VERSION 5.8 ;
BUSBITCHARS "[]" ;
DIVIDERCHAR "/" ;
UNITS
    DATABASE MICRONS 1000 ;
END UNITS

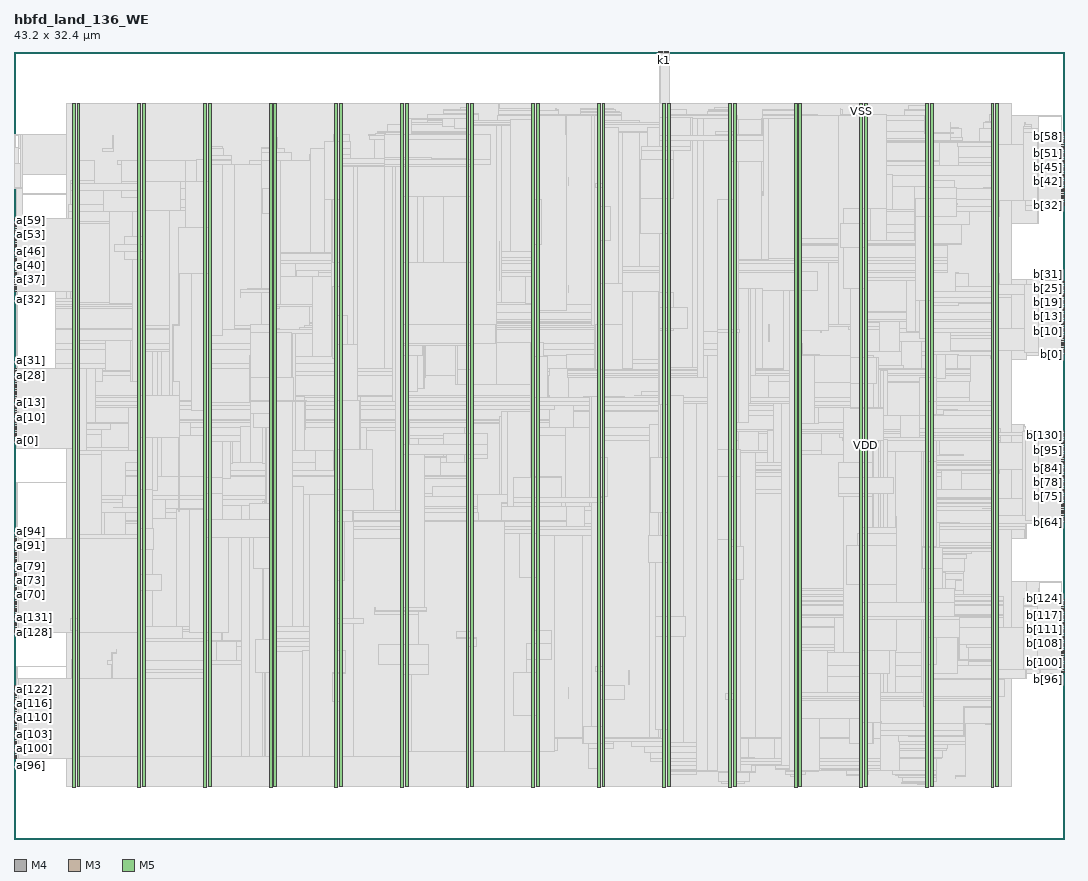
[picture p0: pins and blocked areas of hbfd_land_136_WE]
MACRO hbfd_land_136_WE
  FOREIGN hbfd_land_136_WE 0 0 ;
  CLASS BLOCK ;
  SIZE 43.2 BY 32.4 ;
  PIN a[0]
    DIRECTION INPUT ;
    USE SIGNAL ;
    PORT
      LAYER M4 ;
        RECT  0 16.368 0.084 16.392 ;
    END
  END a[0]
  PIN a[100]
    DIRECTION INPUT ;
    USE SIGNAL ;
    PORT
      LAYER M4 ;
        RECT  0 3.696 0.084 3.72 ;
    END
  END a[100]
  PIN a[101]
    DIRECTION INPUT ;
    USE SIGNAL ;
    PORT
      LAYER M4 ;
        RECT  0 3.792 0.084 3.816 ;
    END
  END a[101]
  PIN a[102]
    DIRECTION INPUT ;
    USE SIGNAL ;
    PORT
      LAYER M4 ;
        RECT  0 3.888 0.084 3.912 ;
    END
  END a[102]
  PIN a[103]
    DIRECTION INPUT ;
    USE SIGNAL ;
    PORT
      LAYER M4 ;
        RECT  0 3.984 0.084 4.008 ;
    END
  END a[103]
  PIN a[104]
    DIRECTION INPUT ;
    USE SIGNAL ;
    PORT
      LAYER M4 ;
        RECT  0 4.08 0.084 4.104 ;
    END
  END a[104]
  PIN a[105]
    DIRECTION INPUT ;
    USE SIGNAL ;
    PORT
      LAYER M4 ;
        RECT  0 4.176 0.084 4.2 ;
    END
  END a[105]
  PIN a[106]
    DIRECTION INPUT ;
    USE SIGNAL ;
    PORT
      LAYER M4 ;
        RECT  0 4.272 0.084 4.296 ;
    END
  END a[106]
  PIN a[107]
    DIRECTION INPUT ;
    USE SIGNAL ;
    PORT
      LAYER M4 ;
        RECT  0 4.368 0.084 4.392 ;
    END
  END a[107]
  PIN a[108]
    DIRECTION INPUT ;
    USE SIGNAL ;
    PORT
      LAYER M4 ;
        RECT  0 4.464 0.084 4.488 ;
    END
  END a[108]
  PIN a[109]
    DIRECTION INPUT ;
    USE SIGNAL ;
    PORT
      LAYER M4 ;
        RECT  0 4.56 0.084 4.584 ;
    END
  END a[109]
  PIN a[10]
    DIRECTION INPUT ;
    USE SIGNAL ;
    PORT
      LAYER M4 ;
        RECT  0 17.328 0.084 17.352 ;
    END
  END a[10]
  PIN a[110]
    DIRECTION INPUT ;
    USE SIGNAL ;
    PORT
      LAYER M4 ;
        RECT  0 4.656 0.084 4.68 ;
    END
  END a[110]
  PIN a[111]
    DIRECTION INPUT ;
    USE SIGNAL ;
    PORT
      LAYER M4 ;
        RECT  0 4.752 0.084 4.776 ;
    END
  END a[111]
  PIN a[112]
    DIRECTION INPUT ;
    USE SIGNAL ;
    PORT
      LAYER M4 ;
        RECT  0 4.848 0.084 4.872 ;
    END
  END a[112]
  PIN a[113]
    DIRECTION INPUT ;
    USE SIGNAL ;
    PORT
      LAYER M4 ;
        RECT  0 4.944 0.084 4.968 ;
    END
  END a[113]
  PIN a[114]
    DIRECTION INPUT ;
    USE SIGNAL ;
    PORT
      LAYER M4 ;
        RECT  0 5.04 0.084 5.064 ;
    END
  END a[114]
  PIN a[115]
    DIRECTION INPUT ;
    USE SIGNAL ;
    PORT
      LAYER M4 ;
        RECT  0 5.136 0.084 5.16 ;
    END
  END a[115]
  PIN a[116]
    DIRECTION INPUT ;
    USE SIGNAL ;
    PORT
      LAYER M4 ;
        RECT  0 5.232 0.084 5.256 ;
    END
  END a[116]
  PIN a[117]
    DIRECTION INPUT ;
    USE SIGNAL ;
    PORT
      LAYER M4 ;
        RECT  0 5.328 0.084 5.352 ;
    END
  END a[117]
  PIN a[118]
    DIRECTION INPUT ;
    USE SIGNAL ;
    PORT
      LAYER M4 ;
        RECT  0 5.424 0.084 5.448 ;
    END
  END a[118]
  PIN a[119]
    DIRECTION INPUT ;
    USE SIGNAL ;
    PORT
      LAYER M4 ;
        RECT  0 5.52 0.084 5.544 ;
    END
  END a[119]
  PIN a[11]
    DIRECTION INPUT ;
    USE SIGNAL ;
    PORT
      LAYER M4 ;
        RECT  0 17.424 0.084 17.448 ;
    END
  END a[11]
  PIN a[120]
    DIRECTION INPUT ;
    USE SIGNAL ;
    PORT
      LAYER M4 ;
        RECT  0 5.616 0.084 5.64 ;
    END
  END a[120]
  PIN a[121]
    DIRECTION INPUT ;
    USE SIGNAL ;
    PORT
      LAYER M4 ;
        RECT  0 5.712 0.084 5.736 ;
    END
  END a[121]
  PIN a[122]
    DIRECTION INPUT ;
    USE SIGNAL ;
    PORT
      LAYER M4 ;
        RECT  0 5.808 0.084 5.832 ;
    END
  END a[122]
  PIN a[123]
    DIRECTION INPUT ;
    USE SIGNAL ;
    PORT
      LAYER M4 ;
        RECT  0 5.904 0.084 5.928 ;
    END
  END a[123]
  PIN a[124]
    DIRECTION INPUT ;
    USE SIGNAL ;
    PORT
      LAYER M4 ;
        RECT  0 6 0.084 6.024 ;
    END
  END a[124]
  PIN a[125]
    DIRECTION INPUT ;
    USE SIGNAL ;
    PORT
      LAYER M4 ;
        RECT  0 6.096 0.084 6.12 ;
    END
  END a[125]
  PIN a[126]
    DIRECTION INPUT ;
    USE SIGNAL ;
    PORT
      LAYER M4 ;
        RECT  0 6.192 0.084 6.216 ;
    END
  END a[126]
  PIN a[127]
    DIRECTION INPUT ;
    USE SIGNAL ;
    PORT
      LAYER M4 ;
        RECT  0 6.288 0.084 6.312 ;
    END
  END a[127]
  PIN a[128]
    DIRECTION INPUT ;
    USE SIGNAL ;
    PORT
      LAYER M4 ;
        RECT  0 8.496 0.084 8.52 ;
    END
  END a[128]
  PIN a[129]
    DIRECTION INPUT ;
    USE SIGNAL ;
    PORT
      LAYER M4 ;
        RECT  0 8.592 0.084 8.616 ;
    END
  END a[129]
  PIN a[12]
    DIRECTION INPUT ;
    USE SIGNAL ;
    PORT
      LAYER M4 ;
        RECT  0 17.52 0.084 17.544 ;
    END
  END a[12]
  PIN a[130]
    DIRECTION INPUT ;
    USE SIGNAL ;
    PORT
      LAYER M4 ;
        RECT  0 8.688 0.084 8.712 ;
    END
  END a[130]
  PIN a[131]
    DIRECTION INPUT ;
    USE SIGNAL ;
    PORT
      LAYER M4 ;
        RECT  0 8.784 0.084 8.808 ;
    END
  END a[131]
  PIN a[132]
    DIRECTION INPUT ;
    USE SIGNAL ;
    PORT
      LAYER M4 ;
        RECT  0 8.88 0.084 8.904 ;
    END
  END a[132]
  PIN a[133]
    DIRECTION INPUT ;
    USE SIGNAL ;
    PORT
      LAYER M4 ;
        RECT  0 8.976 0.084 9 ;
    END
  END a[133]
  PIN a[134]
    DIRECTION INPUT ;
    USE SIGNAL ;
    PORT
      LAYER M4 ;
        RECT  0 9.072 0.084 9.096 ;
    END
  END a[134]
  PIN a[135]
    DIRECTION INPUT ;
    USE SIGNAL ;
    PORT
      LAYER M4 ;
        RECT  0 9.168 0.084 9.192 ;
    END
  END a[135]
  PIN a[13]
    DIRECTION INPUT ;
    USE SIGNAL ;
    PORT
      LAYER M4 ;
        RECT  0 17.616 0.084 17.64 ;
    END
  END a[13]
  PIN a[14]
    DIRECTION INPUT ;
    USE SIGNAL ;
    PORT
      LAYER M4 ;
        RECT  0 17.712 0.084 17.736 ;
    END
  END a[14]
  PIN a[15]
    DIRECTION INPUT ;
    USE SIGNAL ;
    PORT
      LAYER M4 ;
        RECT  0 17.808 0.084 17.832 ;
    END
  END a[15]
  PIN a[16]
    DIRECTION INPUT ;
    USE SIGNAL ;
    PORT
      LAYER M4 ;
        RECT  0 17.904 0.084 17.928 ;
    END
  END a[16]
  PIN a[17]
    DIRECTION INPUT ;
    USE SIGNAL ;
    PORT
      LAYER M4 ;
        RECT  0 18 0.084 18.024 ;
    END
  END a[17]
  PIN a[18]
    DIRECTION INPUT ;
    USE SIGNAL ;
    PORT
      LAYER M4 ;
        RECT  0 18.096 0.084 18.12 ;
    END
  END a[18]
  PIN a[19]
    DIRECTION INPUT ;
    USE SIGNAL ;
    PORT
      LAYER M4 ;
        RECT  0 18.192 0.084 18.216 ;
    END
  END a[19]
  PIN a[1]
    DIRECTION INPUT ;
    USE SIGNAL ;
    PORT
      LAYER M4 ;
        RECT  0 16.464 0.084 16.488 ;
    END
  END a[1]
  PIN a[20]
    DIRECTION INPUT ;
    USE SIGNAL ;
    PORT
      LAYER M4 ;
        RECT  0 18.288 0.084 18.312 ;
    END
  END a[20]
  PIN a[21]
    DIRECTION INPUT ;
    USE SIGNAL ;
    PORT
      LAYER M4 ;
        RECT  0 18.384 0.084 18.408 ;
    END
  END a[21]
  PIN a[22]
    DIRECTION INPUT ;
    USE SIGNAL ;
    PORT
      LAYER M4 ;
        RECT  0 18.48 0.084 18.504 ;
    END
  END a[22]
  PIN a[23]
    DIRECTION INPUT ;
    USE SIGNAL ;
    PORT
      LAYER M4 ;
        RECT  0 18.576 0.084 18.6 ;
    END
  END a[23]
  PIN a[24]
    DIRECTION INPUT ;
    USE SIGNAL ;
    PORT
      LAYER M4 ;
        RECT  0 18.672 0.084 18.696 ;
    END
  END a[24]
  PIN a[25]
    DIRECTION INPUT ;
    USE SIGNAL ;
    PORT
      LAYER M4 ;
        RECT  0 18.768 0.084 18.792 ;
    END
  END a[25]
  PIN a[26]
    DIRECTION INPUT ;
    USE SIGNAL ;
    PORT
      LAYER M4 ;
        RECT  0 18.864 0.084 18.888 ;
    END
  END a[26]
  PIN a[27]
    DIRECTION INPUT ;
    USE SIGNAL ;
    PORT
      LAYER M4 ;
        RECT  0 18.96 0.084 18.984 ;
    END
  END a[27]
  PIN a[28]
    DIRECTION INPUT ;
    USE SIGNAL ;
    PORT
      LAYER M4 ;
        RECT  0 19.056 0.084 19.08 ;
    END
  END a[28]
  PIN a[29]
    DIRECTION INPUT ;
    USE SIGNAL ;
    PORT
      LAYER M4 ;
        RECT  0 19.152 0.084 19.176 ;
    END
  END a[29]
  PIN a[2]
    DIRECTION INPUT ;
    USE SIGNAL ;
    PORT
      LAYER M4 ;
        RECT  0 16.56 0.084 16.584 ;
    END
  END a[2]
  PIN a[30]
    DIRECTION INPUT ;
    USE SIGNAL ;
    PORT
      LAYER M4 ;
        RECT  0 19.248 0.084 19.272 ;
    END
  END a[30]
  PIN a[31]
    DIRECTION INPUT ;
    USE SIGNAL ;
    PORT
      LAYER M4 ;
        RECT  0 19.344 0.084 19.368 ;
    END
  END a[31]
  PIN a[32]
    DIRECTION INPUT ;
    USE SIGNAL ;
    PORT
      LAYER M4 ;
        RECT  0 22.512 0.084 22.536 ;
    END
  END a[32]
  PIN a[33]
    DIRECTION INPUT ;
    USE SIGNAL ;
    PORT
      LAYER M4 ;
        RECT  0 22.608 0.084 22.632 ;
    END
  END a[33]
  PIN a[34]
    DIRECTION INPUT ;
    USE SIGNAL ;
    PORT
      LAYER M4 ;
        RECT  0 22.704 0.084 22.728 ;
    END
  END a[34]
  PIN a[35]
    DIRECTION INPUT ;
    USE SIGNAL ;
    PORT
      LAYER M4 ;
        RECT  0 22.8 0.084 22.824 ;
    END
  END a[35]
  PIN a[36]
    DIRECTION INPUT ;
    USE SIGNAL ;
    PORT
      LAYER M4 ;
        RECT  0 22.896 0.084 22.92 ;
    END
  END a[36]
  PIN a[37]
    DIRECTION INPUT ;
    USE SIGNAL ;
    PORT
      LAYER M4 ;
        RECT  0 22.992 0.084 23.016 ;
    END
  END a[37]
  PIN a[38]
    DIRECTION INPUT ;
    USE SIGNAL ;
    PORT
      LAYER M4 ;
        RECT  0 23.088 0.084 23.112 ;
    END
  END a[38]
  PIN a[39]
    DIRECTION INPUT ;
    USE SIGNAL ;
    PORT
      LAYER M4 ;
        RECT  0 23.184 0.084 23.208 ;
    END
  END a[39]
  PIN a[3]
    DIRECTION INPUT ;
    USE SIGNAL ;
    PORT
      LAYER M4 ;
        RECT  0 16.656 0.084 16.68 ;
    END
  END a[3]
  PIN a[40]
    DIRECTION INPUT ;
    USE SIGNAL ;
    PORT
      LAYER M4 ;
        RECT  0 23.28 0.084 23.304 ;
    END
  END a[40]
  PIN a[41]
    DIRECTION INPUT ;
    USE SIGNAL ;
    PORT
      LAYER M4 ;
        RECT  0 23.376 0.084 23.4 ;
    END
  END a[41]
  PIN a[42]
    DIRECTION INPUT ;
    USE SIGNAL ;
    PORT
      LAYER M4 ;
        RECT  0 23.472 0.084 23.496 ;
    END
  END a[42]
  PIN a[43]
    DIRECTION INPUT ;
    USE SIGNAL ;
    PORT
      LAYER M4 ;
        RECT  0 23.568 0.084 23.592 ;
    END
  END a[43]
  PIN a[44]
    DIRECTION INPUT ;
    USE SIGNAL ;
    PORT
      LAYER M4 ;
        RECT  0 23.664 0.084 23.688 ;
    END
  END a[44]
  PIN a[45]
    DIRECTION INPUT ;
    USE SIGNAL ;
    PORT
      LAYER M4 ;
        RECT  0 23.76 0.084 23.784 ;
    END
  END a[45]
  PIN a[46]
    DIRECTION INPUT ;
    USE SIGNAL ;
    PORT
      LAYER M4 ;
        RECT  0 23.856 0.084 23.88 ;
    END
  END a[46]
  PIN a[47]
    DIRECTION INPUT ;
    USE SIGNAL ;
    PORT
      LAYER M4 ;
        RECT  0 23.952 0.084 23.976 ;
    END
  END a[47]
  PIN a[48]
    DIRECTION INPUT ;
    USE SIGNAL ;
    PORT
      LAYER M4 ;
        RECT  0 24.048 0.084 24.072 ;
    END
  END a[48]
  PIN a[49]
    DIRECTION INPUT ;
    USE SIGNAL ;
    PORT
      LAYER M4 ;
        RECT  0 24.144 0.084 24.168 ;
    END
  END a[49]
  PIN a[4]
    DIRECTION INPUT ;
    USE SIGNAL ;
    PORT
      LAYER M4 ;
        RECT  0 16.752 0.084 16.776 ;
    END
  END a[4]
  PIN a[50]
    DIRECTION INPUT ;
    USE SIGNAL ;
    PORT
      LAYER M4 ;
        RECT  0 24.24 0.084 24.264 ;
    END
  END a[50]
  PIN a[51]
    DIRECTION INPUT ;
    USE SIGNAL ;
    PORT
      LAYER M4 ;
        RECT  0 24.336 0.084 24.36 ;
    END
  END a[51]
  PIN a[52]
    DIRECTION INPUT ;
    USE SIGNAL ;
    PORT
      LAYER M4 ;
        RECT  0 24.432 0.084 24.456 ;
    END
  END a[52]
  PIN a[53]
    DIRECTION INPUT ;
    USE SIGNAL ;
    PORT
      LAYER M4 ;
        RECT  0 24.528 0.084 24.552 ;
    END
  END a[53]
  PIN a[54]
    DIRECTION INPUT ;
    USE SIGNAL ;
    PORT
      LAYER M4 ;
        RECT  0 24.624 0.084 24.648 ;
    END
  END a[54]
  PIN a[55]
    DIRECTION INPUT ;
    USE SIGNAL ;
    PORT
      LAYER M4 ;
        RECT  0 24.72 0.084 24.744 ;
    END
  END a[55]
  PIN a[56]
    DIRECTION INPUT ;
    USE SIGNAL ;
    PORT
      LAYER M4 ;
        RECT  0 24.816 0.084 24.84 ;
    END
  END a[56]
  PIN a[57]
    DIRECTION INPUT ;
    USE SIGNAL ;
    PORT
      LAYER M4 ;
        RECT  0 24.912 0.084 24.936 ;
    END
  END a[57]
  PIN a[58]
    DIRECTION INPUT ;
    USE SIGNAL ;
    PORT
      LAYER M4 ;
        RECT  0 25.008 0.084 25.032 ;
    END
  END a[58]
  PIN a[59]
    DIRECTION INPUT ;
    USE SIGNAL ;
    PORT
      LAYER M4 ;
        RECT  0 25.104 0.084 25.128 ;
    END
  END a[59]
  PIN a[5]
    DIRECTION INPUT ;
    USE SIGNAL ;
    PORT
      LAYER M4 ;
        RECT  0 16.848 0.084 16.872 ;
    END
  END a[5]
  PIN a[60]
    DIRECTION INPUT ;
    USE SIGNAL ;
    PORT
      LAYER M4 ;
        RECT  0 25.2 0.084 25.224 ;
    END
  END a[60]
  PIN a[61]
    DIRECTION INPUT ;
    USE SIGNAL ;
    PORT
      LAYER M4 ;
        RECT  0 25.296 0.084 25.32 ;
    END
  END a[61]
  PIN a[62]
    DIRECTION INPUT ;
    USE SIGNAL ;
    PORT
      LAYER M4 ;
        RECT  0 25.392 0.084 25.416 ;
    END
  END a[62]
  PIN a[63]
    DIRECTION INPUT ;
    USE SIGNAL ;
    PORT
      LAYER M4 ;
        RECT  0 25.488 0.084 25.512 ;
    END
  END a[63]
  PIN a[64]
    DIRECTION INPUT ;
    USE SIGNAL ;
    PORT
      LAYER M4 ;
        RECT  0 9.456 0.084 9.48 ;
    END
  END a[64]
  PIN a[65]
    DIRECTION INPUT ;
    USE SIGNAL ;
    PORT
      LAYER M4 ;
        RECT  0 9.552 0.084 9.576 ;
    END
  END a[65]
  PIN a[66]
    DIRECTION INPUT ;
    USE SIGNAL ;
    PORT
      LAYER M4 ;
        RECT  0 9.648 0.084 9.672 ;
    END
  END a[66]
  PIN a[67]
    DIRECTION INPUT ;
    USE SIGNAL ;
    PORT
      LAYER M4 ;
        RECT  0 9.744 0.084 9.768 ;
    END
  END a[67]
  PIN a[68]
    DIRECTION INPUT ;
    USE SIGNAL ;
    PORT
      LAYER M4 ;
        RECT  0 9.84 0.084 9.864 ;
    END
  END a[68]
  PIN a[69]
    DIRECTION INPUT ;
    USE SIGNAL ;
    PORT
      LAYER M4 ;
        RECT  0 9.936 0.084 9.96 ;
    END
  END a[69]
  PIN a[6]
    DIRECTION INPUT ;
    USE SIGNAL ;
    PORT
      LAYER M4 ;
        RECT  0 16.944 0.084 16.968 ;
    END
  END a[6]
  PIN a[70]
    DIRECTION INPUT ;
    USE SIGNAL ;
    PORT
      LAYER M4 ;
        RECT  0 10.032 0.084 10.056 ;
    END
  END a[70]
  PIN a[71]
    DIRECTION INPUT ;
    USE SIGNAL ;
    PORT
      LAYER M4 ;
        RECT  0 10.128 0.084 10.152 ;
    END
  END a[71]
  PIN a[72]
    DIRECTION INPUT ;
    USE SIGNAL ;
    PORT
      LAYER M4 ;
        RECT  0 10.224 0.084 10.248 ;
    END
  END a[72]
  PIN a[73]
    DIRECTION INPUT ;
    USE SIGNAL ;
    PORT
      LAYER M4 ;
        RECT  0 10.32 0.084 10.344 ;
    END
  END a[73]
  PIN a[74]
    DIRECTION INPUT ;
    USE SIGNAL ;
    PORT
      LAYER M4 ;
        RECT  0 10.416 0.084 10.44 ;
    END
  END a[74]
  PIN a[75]
    DIRECTION INPUT ;
    USE SIGNAL ;
    PORT
      LAYER M4 ;
        RECT  0 10.512 0.084 10.536 ;
    END
  END a[75]
  PIN a[76]
    DIRECTION INPUT ;
    USE SIGNAL ;
    PORT
      LAYER M4 ;
        RECT  0 10.608 0.084 10.632 ;
    END
  END a[76]
  PIN a[77]
    DIRECTION INPUT ;
    USE SIGNAL ;
    PORT
      LAYER M4 ;
        RECT  0 10.704 0.084 10.728 ;
    END
  END a[77]
  PIN a[78]
    DIRECTION INPUT ;
    USE SIGNAL ;
    PORT
      LAYER M4 ;
        RECT  0 10.8 0.084 10.824 ;
    END
  END a[78]
  PIN a[79]
    DIRECTION INPUT ;
    USE SIGNAL ;
    PORT
      LAYER M4 ;
        RECT  0 10.896 0.084 10.92 ;
    END
  END a[79]
  PIN a[7]
    DIRECTION INPUT ;
    USE SIGNAL ;
    PORT
      LAYER M4 ;
        RECT  0 17.04 0.084 17.064 ;
    END
  END a[7]
  PIN a[80]
    DIRECTION INPUT ;
    USE SIGNAL ;
    PORT
      LAYER M4 ;
        RECT  0 10.992 0.084 11.016 ;
    END
  END a[80]
  PIN a[81]
    DIRECTION INPUT ;
    USE SIGNAL ;
    PORT
      LAYER M4 ;
        RECT  0 11.088 0.084 11.112 ;
    END
  END a[81]
  PIN a[82]
    DIRECTION INPUT ;
    USE SIGNAL ;
    PORT
      LAYER M4 ;
        RECT  0 11.184 0.084 11.208 ;
    END
  END a[82]
  PIN a[83]
    DIRECTION INPUT ;
    USE SIGNAL ;
    PORT
      LAYER M4 ;
        RECT  0 11.28 0.084 11.304 ;
    END
  END a[83]
  PIN a[84]
    DIRECTION INPUT ;
    USE SIGNAL ;
    PORT
      LAYER M4 ;
        RECT  0 11.376 0.084 11.4 ;
    END
  END a[84]
  PIN a[85]
    DIRECTION INPUT ;
    USE SIGNAL ;
    PORT
      LAYER M4 ;
        RECT  0 11.472 0.084 11.496 ;
    END
  END a[85]
  PIN a[86]
    DIRECTION INPUT ;
    USE SIGNAL ;
    PORT
      LAYER M4 ;
        RECT  0 11.568 0.084 11.592 ;
    END
  END a[86]
  PIN a[87]
    DIRECTION INPUT ;
    USE SIGNAL ;
    PORT
      LAYER M4 ;
        RECT  0 11.664 0.084 11.688 ;
    END
  END a[87]
  PIN a[88]
    DIRECTION INPUT ;
    USE SIGNAL ;
    PORT
      LAYER M4 ;
        RECT  0 11.76 0.084 11.784 ;
    END
  END a[88]
  PIN a[89]
    DIRECTION INPUT ;
    USE SIGNAL ;
    PORT
      LAYER M4 ;
        RECT  0 11.856 0.084 11.88 ;
    END
  END a[89]
  PIN a[8]
    DIRECTION INPUT ;
    USE SIGNAL ;
    PORT
      LAYER M4 ;
        RECT  0 17.136 0.084 17.16 ;
    END
  END a[8]
  PIN a[90]
    DIRECTION INPUT ;
    USE SIGNAL ;
    PORT
      LAYER M4 ;
        RECT  0 11.952 0.084 11.976 ;
    END
  END a[90]
  PIN a[91]
    DIRECTION INPUT ;
    USE SIGNAL ;
    PORT
      LAYER M4 ;
        RECT  0 12.048 0.084 12.072 ;
    END
  END a[91]
  PIN a[92]
    DIRECTION INPUT ;
    USE SIGNAL ;
    PORT
      LAYER M4 ;
        RECT  0 12.144 0.084 12.168 ;
    END
  END a[92]
  PIN a[93]
    DIRECTION INPUT ;
    USE SIGNAL ;
    PORT
      LAYER M4 ;
        RECT  0 12.24 0.084 12.264 ;
    END
  END a[93]
  PIN a[94]
    DIRECTION INPUT ;
    USE SIGNAL ;
    PORT
      LAYER M4 ;
        RECT  0 12.336 0.084 12.36 ;
    END
  END a[94]
  PIN a[95]
    DIRECTION INPUT ;
    USE SIGNAL ;
    PORT
      LAYER M4 ;
        RECT  0 12.432 0.084 12.456 ;
    END
  END a[95]
  PIN a[96]
    DIRECTION INPUT ;
    USE SIGNAL ;
    PORT
      LAYER M4 ;
        RECT  0 3.312 0.084 3.336 ;
    END
  END a[96]
  PIN a[97]
    DIRECTION INPUT ;
    USE SIGNAL ;
    PORT
      LAYER M4 ;
        RECT  0 3.408 0.084 3.432 ;
    END
  END a[97]
  PIN a[98]
    DIRECTION INPUT ;
    USE SIGNAL ;
    PORT
      LAYER M4 ;
        RECT  0 3.504 0.084 3.528 ;
    END
  END a[98]
  PIN a[99]
    DIRECTION INPUT ;
    USE SIGNAL ;
    PORT
      LAYER M4 ;
        RECT  0 3.6 0.084 3.624 ;
    END
  END a[99]
  PIN a[9]
    DIRECTION INPUT ;
    USE SIGNAL ;
    PORT
      LAYER M4 ;
        RECT  0 17.232 0.084 17.256 ;
    END
  END a[9]
  PIN b[0]
    DIRECTION OUTPUT ;
    USE SIGNAL ;
    PORT
      LAYER M4 ;
        RECT  43.116 19.92 43.2 19.944 ;
    END
  END b[0]
  PIN b[100]
    DIRECTION OUTPUT ;
    USE SIGNAL ;
    PORT
      LAYER M4 ;
        RECT  43.116 7.248 43.2 7.272 ;
    END
  END b[100]
  PIN b[101]
    DIRECTION OUTPUT ;
    USE SIGNAL ;
    PORT
      LAYER M4 ;
        RECT  43.116 7.344 43.2 7.368 ;
    END
  END b[101]
  PIN b[102]
    DIRECTION OUTPUT ;
    USE SIGNAL ;
    PORT
      LAYER M4 ;
        RECT  43.116 7.44 43.2 7.464 ;
    END
  END b[102]
  PIN b[103]
    DIRECTION OUTPUT ;
    USE SIGNAL ;
    PORT
      LAYER M4 ;
        RECT  43.116 7.536 43.2 7.56 ;
    END
  END b[103]
  PIN b[104]
    DIRECTION OUTPUT ;
    USE SIGNAL ;
    PORT
      LAYER M4 ;
        RECT  43.116 7.632 43.2 7.656 ;
    END
  END b[104]
  PIN b[105]
    DIRECTION OUTPUT ;
    USE SIGNAL ;
    PORT
      LAYER M4 ;
        RECT  43.116 7.728 43.2 7.752 ;
    END
  END b[105]
  PIN b[106]
    DIRECTION OUTPUT ;
    USE SIGNAL ;
    PORT
      LAYER M4 ;
        RECT  43.116 7.824 43.2 7.848 ;
    END
  END b[106]
  PIN b[107]
    DIRECTION OUTPUT ;
    USE SIGNAL ;
    PORT
      LAYER M4 ;
        RECT  43.116 7.92 43.2 7.944 ;
    END
  END b[107]
  PIN b[108]
    DIRECTION OUTPUT ;
    USE SIGNAL ;
    PORT
      LAYER M4 ;
        RECT  43.116 8.016 43.2 8.04 ;
    END
  END b[108]
  PIN b[109]
    DIRECTION OUTPUT ;
    USE SIGNAL ;
    PORT
      LAYER M4 ;
        RECT  43.116 8.112 43.2 8.136 ;
    END
  END b[109]
  PIN b[10]
    DIRECTION OUTPUT ;
    USE SIGNAL ;
    PORT
      LAYER M4 ;
        RECT  43.116 20.88 43.2 20.904 ;
    END
  END b[10]
  PIN b[110]
    DIRECTION OUTPUT ;
    USE SIGNAL ;
    PORT
      LAYER M4 ;
        RECT  43.116 8.208 43.2 8.232 ;
    END
  END b[110]
  PIN b[111]
    DIRECTION OUTPUT ;
    USE SIGNAL ;
    PORT
      LAYER M4 ;
        RECT  43.116 8.304 43.2 8.328 ;
    END
  END b[111]
  PIN b[112]
    DIRECTION OUTPUT ;
    USE SIGNAL ;
    PORT
      LAYER M4 ;
        RECT  43.116 8.4 43.2 8.424 ;
    END
  END b[112]
  PIN b[113]
    DIRECTION OUTPUT ;
    USE SIGNAL ;
    PORT
      LAYER M4 ;
        RECT  43.116 8.496 43.2 8.52 ;
    END
  END b[113]
  PIN b[114]
    DIRECTION OUTPUT ;
    USE SIGNAL ;
    PORT
      LAYER M4 ;
        RECT  43.116 8.592 43.2 8.616 ;
    END
  END b[114]
  PIN b[115]
    DIRECTION OUTPUT ;
    USE SIGNAL ;
    PORT
      LAYER M4 ;
        RECT  43.116 8.688 43.2 8.712 ;
    END
  END b[115]
  PIN b[116]
    DIRECTION OUTPUT ;
    USE SIGNAL ;
    PORT
      LAYER M4 ;
        RECT  43.116 8.784 43.2 8.808 ;
    END
  END b[116]
  PIN b[117]
    DIRECTION OUTPUT ;
    USE SIGNAL ;
    PORT
      LAYER M4 ;
        RECT  43.116 8.88 43.2 8.904 ;
    END
  END b[117]
  PIN b[118]
    DIRECTION OUTPUT ;
    USE SIGNAL ;
    PORT
      LAYER M4 ;
        RECT  43.116 8.976 43.2 9 ;
    END
  END b[118]
  PIN b[119]
    DIRECTION OUTPUT ;
    USE SIGNAL ;
    PORT
      LAYER M4 ;
        RECT  43.116 9.072 43.2 9.096 ;
    END
  END b[119]
  PIN b[11]
    DIRECTION OUTPUT ;
    USE SIGNAL ;
    PORT
      LAYER M4 ;
        RECT  43.116 20.976 43.2 21 ;
    END
  END b[11]
  PIN b[120]
    DIRECTION OUTPUT ;
    USE SIGNAL ;
    PORT
      LAYER M4 ;
        RECT  43.116 9.168 43.2 9.192 ;
    END
  END b[120]
  PIN b[121]
    DIRECTION OUTPUT ;
    USE SIGNAL ;
    PORT
      LAYER M4 ;
        RECT  43.116 9.264 43.2 9.288 ;
    END
  END b[121]
  PIN b[122]
    DIRECTION OUTPUT ;
    USE SIGNAL ;
    PORT
      LAYER M4 ;
        RECT  43.116 9.36 43.2 9.384 ;
    END
  END b[122]
  PIN b[123]
    DIRECTION OUTPUT ;
    USE SIGNAL ;
    PORT
      LAYER M4 ;
        RECT  43.116 9.456 43.2 9.48 ;
    END
  END b[123]
  PIN b[124]
    DIRECTION OUTPUT ;
    USE SIGNAL ;
    PORT
      LAYER M4 ;
        RECT  43.116 9.552 43.2 9.576 ;
    END
  END b[124]
  PIN b[125]
    DIRECTION OUTPUT ;
    USE SIGNAL ;
    PORT
      LAYER M4 ;
        RECT  43.116 9.648 43.2 9.672 ;
    END
  END b[125]
  PIN b[126]
    DIRECTION OUTPUT ;
    USE SIGNAL ;
    PORT
      LAYER M4 ;
        RECT  43.116 9.744 43.2 9.768 ;
    END
  END b[126]
  PIN b[127]
    DIRECTION OUTPUT ;
    USE SIGNAL ;
    PORT
      LAYER M4 ;
        RECT  43.116 9.84 43.2 9.864 ;
    END
  END b[127]
  PIN b[128]
    DIRECTION OUTPUT ;
    USE SIGNAL ;
    PORT
      LAYER M4 ;
        RECT  43.116 16.08 43.2 16.104 ;
    END
  END b[128]
  PIN b[129]
    DIRECTION OUTPUT ;
    USE SIGNAL ;
    PORT
      LAYER M4 ;
        RECT  43.116 16.176 43.2 16.2 ;
    END
  END b[129]
  PIN b[12]
    DIRECTION OUTPUT ;
    USE SIGNAL ;
    PORT
      LAYER M4 ;
        RECT  43.116 21.072 43.2 21.096 ;
    END
  END b[12]
  PIN b[130]
    DIRECTION OUTPUT ;
    USE SIGNAL ;
    PORT
      LAYER M4 ;
        RECT  43.116 16.272 43.2 16.296 ;
    END
  END b[130]
  PIN b[131]
    DIRECTION OUTPUT ;
    USE SIGNAL ;
    PORT
      LAYER M4 ;
        RECT  43.116 16.368 43.2 16.392 ;
    END
  END b[131]
  PIN b[132]
    DIRECTION OUTPUT ;
    USE SIGNAL ;
    PORT
      LAYER M4 ;
        RECT  43.116 16.464 43.2 16.488 ;
    END
  END b[132]
  PIN b[133]
    DIRECTION OUTPUT ;
    USE SIGNAL ;
    PORT
      LAYER M4 ;
        RECT  43.116 16.56 43.2 16.584 ;
    END
  END b[133]
  PIN b[134]
    DIRECTION OUTPUT ;
    USE SIGNAL ;
    PORT
      LAYER M4 ;
        RECT  43.116 16.656 43.2 16.68 ;
    END
  END b[134]
  PIN b[135]
    DIRECTION OUTPUT ;
    USE SIGNAL ;
    PORT
      LAYER M4 ;
        RECT  43.116 16.752 43.2 16.776 ;
    END
  END b[135]
  PIN b[13]
    DIRECTION OUTPUT ;
    USE SIGNAL ;
    PORT
      LAYER M4 ;
        RECT  43.116 21.168 43.2 21.192 ;
    END
  END b[13]
  PIN b[14]
    DIRECTION OUTPUT ;
    USE SIGNAL ;
    PORT
      LAYER M4 ;
        RECT  43.116 21.264 43.2 21.288 ;
    END
  END b[14]
  PIN b[15]
    DIRECTION OUTPUT ;
    USE SIGNAL ;
    PORT
      LAYER M4 ;
        RECT  43.116 21.36 43.2 21.384 ;
    END
  END b[15]
  PIN b[16]
    DIRECTION OUTPUT ;
    USE SIGNAL ;
    PORT
      LAYER M4 ;
        RECT  43.116 21.456 43.2 21.48 ;
    END
  END b[16]
  PIN b[17]
    DIRECTION OUTPUT ;
    USE SIGNAL ;
    PORT
      LAYER M4 ;
        RECT  43.116 21.552 43.2 21.576 ;
    END
  END b[17]
  PIN b[18]
    DIRECTION OUTPUT ;
    USE SIGNAL ;
    PORT
      LAYER M4 ;
        RECT  43.116 21.648 43.2 21.672 ;
    END
  END b[18]
  PIN b[19]
    DIRECTION OUTPUT ;
    USE SIGNAL ;
    PORT
      LAYER M4 ;
        RECT  43.116 21.744 43.2 21.768 ;
    END
  END b[19]
  PIN b[1]
    DIRECTION OUTPUT ;
    USE SIGNAL ;
    PORT
      LAYER M4 ;
        RECT  43.116 20.016 43.2 20.04 ;
    END
  END b[1]
  PIN b[20]
    DIRECTION OUTPUT ;
    USE SIGNAL ;
    PORT
      LAYER M4 ;
        RECT  43.116 21.84 43.2 21.864 ;
    END
  END b[20]
  PIN b[21]
    DIRECTION OUTPUT ;
    USE SIGNAL ;
    PORT
      LAYER M4 ;
        RECT  43.116 21.936 43.2 21.96 ;
    END
  END b[21]
  PIN b[22]
    DIRECTION OUTPUT ;
    USE SIGNAL ;
    PORT
      LAYER M4 ;
        RECT  43.116 22.032 43.2 22.056 ;
    END
  END b[22]
  PIN b[23]
    DIRECTION OUTPUT ;
    USE SIGNAL ;
    PORT
      LAYER M4 ;
        RECT  43.116 22.128 43.2 22.152 ;
    END
  END b[23]
  PIN b[24]
    DIRECTION OUTPUT ;
    USE SIGNAL ;
    PORT
      LAYER M4 ;
        RECT  43.116 22.224 43.2 22.248 ;
    END
  END b[24]
  PIN b[25]
    DIRECTION OUTPUT ;
    USE SIGNAL ;
    PORT
      LAYER M4 ;
        RECT  43.116 22.32 43.2 22.344 ;
    END
  END b[25]
  PIN b[26]
    DIRECTION OUTPUT ;
    USE SIGNAL ;
    PORT
      LAYER M4 ;
        RECT  43.116 22.416 43.2 22.44 ;
    END
  END b[26]
  PIN b[27]
    DIRECTION OUTPUT ;
    USE SIGNAL ;
    PORT
      LAYER M4 ;
        RECT  43.116 22.512 43.2 22.536 ;
    END
  END b[27]
  PIN b[28]
    DIRECTION OUTPUT ;
    USE SIGNAL ;
    PORT
      LAYER M4 ;
        RECT  43.116 22.608 43.2 22.632 ;
    END
  END b[28]
  PIN b[29]
    DIRECTION OUTPUT ;
    USE SIGNAL ;
    PORT
      LAYER M4 ;
        RECT  43.116 22.704 43.2 22.728 ;
    END
  END b[29]
  PIN b[2]
    DIRECTION OUTPUT ;
    USE SIGNAL ;
    PORT
      LAYER M4 ;
        RECT  43.116 20.112 43.2 20.136 ;
    END
  END b[2]
  PIN b[30]
    DIRECTION OUTPUT ;
    USE SIGNAL ;
    PORT
      LAYER M4 ;
        RECT  43.116 22.8 43.2 22.824 ;
    END
  END b[30]
  PIN b[31]
    DIRECTION OUTPUT ;
    USE SIGNAL ;
    PORT
      LAYER M4 ;
        RECT  43.116 22.896 43.2 22.92 ;
    END
  END b[31]
  PIN b[32]
    DIRECTION OUTPUT ;
    USE SIGNAL ;
    PORT
      LAYER M4 ;
        RECT  43.116 26.064 43.2 26.088 ;
    END
  END b[32]
  PIN b[33]
    DIRECTION OUTPUT ;
    USE SIGNAL ;
    PORT
      LAYER M4 ;
        RECT  43.116 26.16 43.2 26.184 ;
    END
  END b[33]
  PIN b[34]
    DIRECTION OUTPUT ;
    USE SIGNAL ;
    PORT
      LAYER M4 ;
        RECT  43.116 26.256 43.2 26.28 ;
    END
  END b[34]
  PIN b[35]
    DIRECTION OUTPUT ;
    USE SIGNAL ;
    PORT
      LAYER M4 ;
        RECT  43.116 26.352 43.2 26.376 ;
    END
  END b[35]
  PIN b[36]
    DIRECTION OUTPUT ;
    USE SIGNAL ;
    PORT
      LAYER M4 ;
        RECT  43.116 26.448 43.2 26.472 ;
    END
  END b[36]
  PIN b[37]
    DIRECTION OUTPUT ;
    USE SIGNAL ;
    PORT
      LAYER M4 ;
        RECT  43.116 26.544 43.2 26.568 ;
    END
  END b[37]
  PIN b[38]
    DIRECTION OUTPUT ;
    USE SIGNAL ;
    PORT
      LAYER M4 ;
        RECT  43.116 26.64 43.2 26.664 ;
    END
  END b[38]
  PIN b[39]
    DIRECTION OUTPUT ;
    USE SIGNAL ;
    PORT
      LAYER M4 ;
        RECT  43.116 26.736 43.2 26.76 ;
    END
  END b[39]
  PIN b[3]
    DIRECTION OUTPUT ;
    USE SIGNAL ;
    PORT
      LAYER M4 ;
        RECT  43.116 20.208 43.2 20.232 ;
    END
  END b[3]
  PIN b[40]
    DIRECTION OUTPUT ;
    USE SIGNAL ;
    PORT
      LAYER M4 ;
        RECT  43.116 26.832 43.2 26.856 ;
    END
  END b[40]
  PIN b[41]
    DIRECTION OUTPUT ;
    USE SIGNAL ;
    PORT
      LAYER M4 ;
        RECT  43.116 26.928 43.2 26.952 ;
    END
  END b[41]
  PIN b[42]
    DIRECTION OUTPUT ;
    USE SIGNAL ;
    PORT
      LAYER M4 ;
        RECT  43.116 27.024 43.2 27.048 ;
    END
  END b[42]
  PIN b[43]
    DIRECTION OUTPUT ;
    USE SIGNAL ;
    PORT
      LAYER M4 ;
        RECT  43.116 27.12 43.2 27.144 ;
    END
  END b[43]
  PIN b[44]
    DIRECTION OUTPUT ;
    USE SIGNAL ;
    PORT
      LAYER M4 ;
        RECT  43.116 27.216 43.2 27.24 ;
    END
  END b[44]
  PIN b[45]
    DIRECTION OUTPUT ;
    USE SIGNAL ;
    PORT
      LAYER M4 ;
        RECT  43.116 27.312 43.2 27.336 ;
    END
  END b[45]
  PIN b[46]
    DIRECTION OUTPUT ;
    USE SIGNAL ;
    PORT
      LAYER M4 ;
        RECT  43.116 27.408 43.2 27.432 ;
    END
  END b[46]
  PIN b[47]
    DIRECTION OUTPUT ;
    USE SIGNAL ;
    PORT
      LAYER M4 ;
        RECT  43.116 27.504 43.2 27.528 ;
    END
  END b[47]
  PIN b[48]
    DIRECTION OUTPUT ;
    USE SIGNAL ;
    PORT
      LAYER M4 ;
        RECT  43.116 27.6 43.2 27.624 ;
    END
  END b[48]
  PIN b[49]
    DIRECTION OUTPUT ;
    USE SIGNAL ;
    PORT
      LAYER M4 ;
        RECT  43.116 27.696 43.2 27.72 ;
    END
  END b[49]
  PIN b[4]
    DIRECTION OUTPUT ;
    USE SIGNAL ;
    PORT
      LAYER M4 ;
        RECT  43.116 20.304 43.2 20.328 ;
    END
  END b[4]
  PIN b[50]
    DIRECTION OUTPUT ;
    USE SIGNAL ;
    PORT
      LAYER M4 ;
        RECT  43.116 27.792 43.2 27.816 ;
    END
  END b[50]
  PIN b[51]
    DIRECTION OUTPUT ;
    USE SIGNAL ;
    PORT
      LAYER M4 ;
        RECT  43.116 27.888 43.2 27.912 ;
    END
  END b[51]
  PIN b[52]
    DIRECTION OUTPUT ;
    USE SIGNAL ;
    PORT
      LAYER M4 ;
        RECT  43.116 27.984 43.2 28.008 ;
    END
  END b[52]
  PIN b[53]
    DIRECTION OUTPUT ;
    USE SIGNAL ;
    PORT
      LAYER M4 ;
        RECT  43.116 28.08 43.2 28.104 ;
    END
  END b[53]
  PIN b[54]
    DIRECTION OUTPUT ;
    USE SIGNAL ;
    PORT
      LAYER M4 ;
        RECT  43.116 28.176 43.2 28.2 ;
    END
  END b[54]
  PIN b[55]
    DIRECTION OUTPUT ;
    USE SIGNAL ;
    PORT
      LAYER M4 ;
        RECT  43.116 28.272 43.2 28.296 ;
    END
  END b[55]
  PIN b[56]
    DIRECTION OUTPUT ;
    USE SIGNAL ;
    PORT
      LAYER M4 ;
        RECT  43.116 28.368 43.2 28.392 ;
    END
  END b[56]
  PIN b[57]
    DIRECTION OUTPUT ;
    USE SIGNAL ;
    PORT
      LAYER M4 ;
        RECT  43.116 28.464 43.2 28.488 ;
    END
  END b[57]
  PIN b[58]
    DIRECTION OUTPUT ;
    USE SIGNAL ;
    PORT
      LAYER M4 ;
        RECT  43.116 28.56 43.2 28.584 ;
    END
  END b[58]
  PIN b[59]
    DIRECTION OUTPUT ;
    USE SIGNAL ;
    PORT
      LAYER M4 ;
        RECT  43.116 28.656 43.2 28.68 ;
    END
  END b[59]
  PIN b[5]
    DIRECTION OUTPUT ;
    USE SIGNAL ;
    PORT
      LAYER M4 ;
        RECT  43.116 20.4 43.2 20.424 ;
    END
  END b[5]
  PIN b[60]
    DIRECTION OUTPUT ;
    USE SIGNAL ;
    PORT
      LAYER M4 ;
        RECT  43.116 28.752 43.2 28.776 ;
    END
  END b[60]
  PIN b[61]
    DIRECTION OUTPUT ;
    USE SIGNAL ;
    PORT
      LAYER M4 ;
        RECT  43.116 28.848 43.2 28.872 ;
    END
  END b[61]
  PIN b[62]
    DIRECTION OUTPUT ;
    USE SIGNAL ;
    PORT
      LAYER M4 ;
        RECT  43.116 28.944 43.2 28.968 ;
    END
  END b[62]
  PIN b[63]
    DIRECTION OUTPUT ;
    USE SIGNAL ;
    PORT
      LAYER M4 ;
        RECT  43.116 29.04 43.2 29.064 ;
    END
  END b[63]
  PIN b[64]
    DIRECTION OUTPUT ;
    USE SIGNAL ;
    PORT
      LAYER M4 ;
        RECT  43.116 13.008 43.2 13.032 ;
    END
  END b[64]
  PIN b[65]
    DIRECTION OUTPUT ;
    USE SIGNAL ;
    PORT
      LAYER M4 ;
        RECT  43.116 13.104 43.2 13.128 ;
    END
  END b[65]
  PIN b[66]
    DIRECTION OUTPUT ;
    USE SIGNAL ;
    PORT
      LAYER M4 ;
        RECT  43.116 13.2 43.2 13.224 ;
    END
  END b[66]
  PIN b[67]
    DIRECTION OUTPUT ;
    USE SIGNAL ;
    PORT
      LAYER M4 ;
        RECT  43.116 13.296 43.2 13.32 ;
    END
  END b[67]
  PIN b[68]
    DIRECTION OUTPUT ;
    USE SIGNAL ;
    PORT
      LAYER M4 ;
        RECT  43.116 13.392 43.2 13.416 ;
    END
  END b[68]
  PIN b[69]
    DIRECTION OUTPUT ;
    USE SIGNAL ;
    PORT
      LAYER M4 ;
        RECT  43.116 13.488 43.2 13.512 ;
    END
  END b[69]
  PIN b[6]
    DIRECTION OUTPUT ;
    USE SIGNAL ;
    PORT
      LAYER M4 ;
        RECT  43.116 20.496 43.2 20.52 ;
    END
  END b[6]
  PIN b[70]
    DIRECTION OUTPUT ;
    USE SIGNAL ;
    PORT
      LAYER M4 ;
        RECT  43.116 13.584 43.2 13.608 ;
    END
  END b[70]
  PIN b[71]
    DIRECTION OUTPUT ;
    USE SIGNAL ;
    PORT
      LAYER M4 ;
        RECT  43.116 13.68 43.2 13.704 ;
    END
  END b[71]
  PIN b[72]
    DIRECTION OUTPUT ;
    USE SIGNAL ;
    PORT
      LAYER M4 ;
        RECT  43.116 13.776 43.2 13.8 ;
    END
  END b[72]
  PIN b[73]
    DIRECTION OUTPUT ;
    USE SIGNAL ;
    PORT
      LAYER M4 ;
        RECT  43.116 13.872 43.2 13.896 ;
    END
  END b[73]
  PIN b[74]
    DIRECTION OUTPUT ;
    USE SIGNAL ;
    PORT
      LAYER M4 ;
        RECT  43.116 13.968 43.2 13.992 ;
    END
  END b[74]
  PIN b[75]
    DIRECTION OUTPUT ;
    USE SIGNAL ;
    PORT
      LAYER M4 ;
        RECT  43.116 14.064 43.2 14.088 ;
    END
  END b[75]
  PIN b[76]
    DIRECTION OUTPUT ;
    USE SIGNAL ;
    PORT
      LAYER M4 ;
        RECT  43.116 14.16 43.2 14.184 ;
    END
  END b[76]
  PIN b[77]
    DIRECTION OUTPUT ;
    USE SIGNAL ;
    PORT
      LAYER M4 ;
        RECT  43.116 14.256 43.2 14.28 ;
    END
  END b[77]
  PIN b[78]
    DIRECTION OUTPUT ;
    USE SIGNAL ;
    PORT
      LAYER M4 ;
        RECT  43.116 14.352 43.2 14.376 ;
    END
  END b[78]
  PIN b[79]
    DIRECTION OUTPUT ;
    USE SIGNAL ;
    PORT
      LAYER M4 ;
        RECT  43.116 14.448 43.2 14.472 ;
    END
  END b[79]
  PIN b[7]
    DIRECTION OUTPUT ;
    USE SIGNAL ;
    PORT
      LAYER M4 ;
        RECT  43.116 20.592 43.2 20.616 ;
    END
  END b[7]
  PIN b[80]
    DIRECTION OUTPUT ;
    USE SIGNAL ;
    PORT
      LAYER M4 ;
        RECT  43.116 14.544 43.2 14.568 ;
    END
  END b[80]
  PIN b[81]
    DIRECTION OUTPUT ;
    USE SIGNAL ;
    PORT
      LAYER M4 ;
        RECT  43.116 14.64 43.2 14.664 ;
    END
  END b[81]
  PIN b[82]
    DIRECTION OUTPUT ;
    USE SIGNAL ;
    PORT
      LAYER M4 ;
        RECT  43.116 14.736 43.2 14.76 ;
    END
  END b[82]
  PIN b[83]
    DIRECTION OUTPUT ;
    USE SIGNAL ;
    PORT
      LAYER M4 ;
        RECT  43.116 14.832 43.2 14.856 ;
    END
  END b[83]
  PIN b[84]
    DIRECTION OUTPUT ;
    USE SIGNAL ;
    PORT
      LAYER M4 ;
        RECT  43.116 14.928 43.2 14.952 ;
    END
  END b[84]
  PIN b[85]
    DIRECTION OUTPUT ;
    USE SIGNAL ;
    PORT
      LAYER M4 ;
        RECT  43.116 15.024 43.2 15.048 ;
    END
  END b[85]
  PIN b[86]
    DIRECTION OUTPUT ;
    USE SIGNAL ;
    PORT
      LAYER M4 ;
        RECT  43.116 15.12 43.2 15.144 ;
    END
  END b[86]
  PIN b[87]
    DIRECTION OUTPUT ;
    USE SIGNAL ;
    PORT
      LAYER M4 ;
        RECT  43.116 15.216 43.2 15.24 ;
    END
  END b[87]
  PIN b[88]
    DIRECTION OUTPUT ;
    USE SIGNAL ;
    PORT
      LAYER M4 ;
        RECT  43.116 15.312 43.2 15.336 ;
    END
  END b[88]
  PIN b[89]
    DIRECTION OUTPUT ;
    USE SIGNAL ;
    PORT
      LAYER M4 ;
        RECT  43.116 15.408 43.2 15.432 ;
    END
  END b[89]
  PIN b[8]
    DIRECTION OUTPUT ;
    USE SIGNAL ;
    PORT
      LAYER M4 ;
        RECT  43.116 20.688 43.2 20.712 ;
    END
  END b[8]
  PIN b[90]
    DIRECTION OUTPUT ;
    USE SIGNAL ;
    PORT
      LAYER M4 ;
        RECT  43.116 15.504 43.2 15.528 ;
    END
  END b[90]
  PIN b[91]
    DIRECTION OUTPUT ;
    USE SIGNAL ;
    PORT
      LAYER M4 ;
        RECT  43.116 15.6 43.2 15.624 ;
    END
  END b[91]
  PIN b[92]
    DIRECTION OUTPUT ;
    USE SIGNAL ;
    PORT
      LAYER M4 ;
        RECT  43.116 15.696 43.2 15.72 ;
    END
  END b[92]
  PIN b[93]
    DIRECTION OUTPUT ;
    USE SIGNAL ;
    PORT
      LAYER M4 ;
        RECT  43.116 15.792 43.2 15.816 ;
    END
  END b[93]
  PIN b[94]
    DIRECTION OUTPUT ;
    USE SIGNAL ;
    PORT
      LAYER M4 ;
        RECT  43.116 15.888 43.2 15.912 ;
    END
  END b[94]
  PIN b[95]
    DIRECTION OUTPUT ;
    USE SIGNAL ;
    PORT
      LAYER M4 ;
        RECT  43.116 15.984 43.2 16.008 ;
    END
  END b[95]
  PIN b[96]
    DIRECTION OUTPUT ;
    USE SIGNAL ;
    PORT
      LAYER M4 ;
        RECT  43.116 6.864 43.2 6.888 ;
    END
  END b[96]
  PIN b[97]
    DIRECTION OUTPUT ;
    USE SIGNAL ;
    PORT
      LAYER M4 ;
        RECT  43.116 6.96 43.2 6.984 ;
    END
  END b[97]
  PIN b[98]
    DIRECTION OUTPUT ;
    USE SIGNAL ;
    PORT
      LAYER M4 ;
        RECT  43.116 7.056 43.2 7.08 ;
    END
  END b[98]
  PIN b[99]
    DIRECTION OUTPUT ;
    USE SIGNAL ;
    PORT
      LAYER M4 ;
        RECT  43.116 7.152 43.2 7.176 ;
    END
  END b[99]
  PIN b[9]
    DIRECTION OUTPUT ;
    USE SIGNAL ;
    PORT
      LAYER M4 ;
        RECT  43.116 20.784 43.2 20.808 ;
    END
  END b[9]
  PIN ck
    DIRECTION INPUT ;
    USE SIGNAL ;
    PORT
      LAYER M3 ;
        RECT  26.532 32.363 26.55 32.4 ;
    END
  END ck
  PIN ckf
    DIRECTION INPUT ;
    USE SIGNAL ;
    PORT
      LAYER M4 ;
        RECT  0 9.264 0.084 9.288 ;
    END
  END ckf
  PIN ea
    DIRECTION INPUT ;
    USE SIGNAL ;
    PORT
      LAYER M4 ;
        RECT  0 9.36 0.084 9.384 ;
    END
  END ea
  PIN fault
    DIRECTION OUTPUT ;
    USE SIGNAL ;
    PORT
      LAYER M3 ;
        RECT  26.604 32.363 26.622 32.4 ;
    END
  END fault
  PIN k0
    DIRECTION INPUT ;
    USE SIGNAL ;
    PORT
      LAYER M3 ;
        RECT  26.676 32.363 26.694 32.4 ;
    END
  END k0
  PIN k1
    DIRECTION INPUT ;
    USE SIGNAL ;
    PORT
      LAYER M3 ;
        RECT  26.748 32.363 26.766 32.4 ;
    END
  END k1
  PIN k2
    DIRECTION INPUT ;
    USE SIGNAL ;
    PORT
      LAYER M3 ;
        RECT  26.82 32.363 26.838 32.4 ;
    END
  END k2
  PIN rs
    DIRECTION INPUT ;
    USE SIGNAL ;
    PORT
      LAYER M3 ;
        RECT  26.892 32.363 26.91 32.4 ;
    END
  END rs
  PIN VDD
    DIRECTION INOUT ;
    USE POWER ;
    PORT
      LAYER M5 ;
        RECT  40.392 2.151 40.512 30.249 ;
        RECT  37.692 2.151 37.812 30.249 ;
        RECT  34.992 2.151 35.112 30.249 ;
        RECT  32.292 2.151 32.412 30.249 ;
        RECT  29.592 2.151 29.712 30.249 ;
        RECT  26.892 2.151 27.012 30.249 ;
        RECT  24.192 2.151 24.312 30.249 ;
        RECT  21.492 2.151 21.612 30.249 ;
        RECT  18.792 2.151 18.912 30.249 ;
        RECT  16.092 2.151 16.212 30.249 ;
        RECT  13.392 2.151 13.512 30.249 ;
        RECT  10.692 2.151 10.812 30.249 ;
        RECT  7.992 2.151 8.112 30.249 ;
        RECT  5.292 2.151 5.412 30.249 ;
        RECT  2.592 2.151 2.712 30.249 ;
    END
  END VDD
  PIN VSS
    DIRECTION INOUT ;
    USE GROUND ;
    PORT
      LAYER M5 ;
        RECT  40.2 2.137 40.32 30.263 ;
        RECT  37.5 2.137 37.62 30.263 ;
        RECT  34.8 2.137 34.92 30.263 ;
        RECT  32.1 2.137 32.22 30.263 ;
        RECT  29.4 2.137 29.52 30.263 ;
        RECT  26.7 2.137 26.82 30.263 ;
        RECT  24 2.137 24.12 30.263 ;
        RECT  21.3 2.137 21.42 30.263 ;
        RECT  18.6 2.137 18.72 30.263 ;
        RECT  15.9 2.137 16.02 30.263 ;
        RECT  13.2 2.137 13.32 30.263 ;
        RECT  10.5 2.137 10.62 30.263 ;
        RECT  7.8 2.137 7.92 30.263 ;
        RECT  5.1 2.137 5.22 30.263 ;
        RECT  2.4 2.137 2.52 30.263 ;
    END
  END VSS
  OBS
    LAYER RVTN ;
     RECT  2.16 2.16 41.04 2.295 ;
     RECT  2.16 2.565 41.04 2.835 ;
     RECT  2.16 3.105 41.04 3.375 ;
     RECT  2.16 3.645 41.04 3.915 ;
     RECT  2.16 4.185 41.04 4.455 ;
     RECT  2.16 4.725 41.04 4.995 ;
     RECT  2.16 5.265 41.04 5.535 ;
     RECT  2.16 5.805 41.04 6.075 ;
     RECT  2.16 6.345 41.04 6.615 ;
     RECT  2.16 6.885 41.04 7.155 ;
     RECT  2.16 7.425 41.04 7.695 ;
     RECT  2.16 7.965 41.04 8.235 ;
     RECT  2.16 8.505 41.04 8.775 ;
     RECT  2.16 9.045 41.04 9.315 ;
     RECT  2.16 9.585 41.04 9.855 ;
     RECT  2.16 10.125 41.04 10.395 ;
     RECT  2.16 10.665 41.04 10.935 ;
     RECT  2.16 11.205 41.04 11.475 ;
     RECT  2.16 11.745 41.04 12.015 ;
     RECT  2.16 12.285 41.04 12.555 ;
     RECT  2.16 12.825 41.04 13.095 ;
     RECT  2.16 13.365 41.04 13.635 ;
     RECT  2.16 13.905 41.04 14.175 ;
     RECT  2.16 14.445 41.04 14.715 ;
     RECT  2.16 14.985 41.04 15.255 ;
     RECT  2.16 15.525 41.04 15.795 ;
     RECT  2.16 16.065 41.04 16.335 ;
     RECT  2.16 16.605 41.04 16.875 ;
     RECT  2.16 17.145 41.04 17.415 ;
     RECT  2.16 17.685 41.04 17.955 ;
     RECT  2.16 18.225 41.04 18.495 ;
     RECT  2.16 18.765 41.04 19.035 ;
     RECT  2.16 19.305 41.04 19.575 ;
     RECT  2.16 19.845 41.04 20.115 ;
     RECT  2.16 20.385 41.04 20.655 ;
     RECT  2.16 20.925 41.04 21.195 ;
     RECT  2.16 21.465 41.04 21.735 ;
     RECT  2.16 22.005 41.04 22.275 ;
     RECT  2.16 22.545 41.04 22.815 ;
     RECT  2.16 23.085 41.04 23.355 ;
     RECT  2.16 23.625 41.04 23.895 ;
     RECT  2.16 24.165 41.04 24.435 ;
     RECT  2.16 24.705 41.04 24.975 ;
     RECT  2.16 25.245 41.04 25.515 ;
     RECT  2.16 25.785 41.04 26.055 ;
     RECT  2.16 26.325 41.04 26.595 ;
     RECT  2.16 26.865 41.04 27.135 ;
     RECT  2.16 27.405 41.04 27.675 ;
     RECT  2.16 27.945 41.04 28.215 ;
     RECT  2.16 28.485 41.04 28.755 ;
     RECT  2.16 29.025 41.04 29.295 ;
     RECT  2.16 29.565 41.04 29.835 ;
     RECT  2.16 30.105 41.04 30.24 ;
    LAYER RVTP ;
     RECT  2.16 2.295 41.04 2.565 ;
     RECT  2.16 2.835 41.04 3.105 ;
     RECT  2.16 3.375 41.04 3.645 ;
     RECT  2.16 3.915 41.04 4.185 ;
     RECT  2.16 4.455 41.04 4.725 ;
     RECT  2.16 4.995 41.04 5.265 ;
     RECT  2.16 5.535 41.04 5.805 ;
     RECT  2.16 6.075 41.04 6.345 ;
     RECT  2.16 6.615 41.04 6.885 ;
     RECT  2.16 7.155 41.04 7.425 ;
     RECT  2.16 7.695 41.04 7.965 ;
     RECT  2.16 8.235 41.04 8.505 ;
     RECT  2.16 8.775 41.04 9.045 ;
     RECT  2.16 9.315 41.04 9.585 ;
     RECT  2.16 9.855 41.04 10.125 ;
     RECT  2.16 10.395 41.04 10.665 ;
     RECT  2.16 10.935 41.04 11.205 ;
     RECT  2.16 11.475 41.04 11.745 ;
     RECT  2.16 12.015 41.04 12.285 ;
     RECT  2.16 12.555 41.04 12.825 ;
     RECT  2.16 13.095 41.04 13.365 ;
     RECT  2.16 13.635 41.04 13.905 ;
     RECT  2.16 14.175 41.04 14.445 ;
     RECT  2.16 14.715 41.04 14.985 ;
     RECT  2.16 15.255 41.04 15.525 ;
     RECT  2.16 15.795 41.04 16.065 ;
     RECT  2.16 16.335 41.04 16.605 ;
     RECT  2.16 16.875 41.04 17.145 ;
     RECT  2.16 17.415 41.04 17.685 ;
     RECT  2.16 17.955 41.04 18.225 ;
     RECT  2.16 18.495 41.04 18.765 ;
     RECT  2.16 19.035 41.04 19.305 ;
     RECT  2.16 19.575 41.04 19.845 ;
     RECT  2.16 20.115 41.04 20.385 ;
     RECT  2.16 20.655 41.04 20.925 ;
     RECT  2.16 21.195 41.04 21.465 ;
     RECT  2.16 21.735 41.04 22.005 ;
     RECT  2.16 22.275 41.04 22.545 ;
     RECT  2.16 22.815 41.04 23.085 ;
     RECT  2.16 23.355 41.04 23.625 ;
     RECT  2.16 23.895 41.04 24.165 ;
     RECT  2.16 24.435 41.04 24.705 ;
     RECT  2.16 24.975 41.04 25.245 ;
     RECT  2.16 25.515 41.04 25.785 ;
     RECT  2.16 26.055 41.04 26.325 ;
     RECT  2.16 26.595 41.04 26.865 ;
     RECT  2.16 27.135 41.04 27.405 ;
     RECT  2.16 27.675 41.04 27.945 ;
     RECT  2.16 28.215 41.04 28.485 ;
     RECT  2.16 28.755 41.04 29.025 ;
     RECT  2.16 29.295 41.04 29.565 ;
     RECT  2.16 29.835 41.04 30.105 ;
    LAYER M1 ;
     RECT  2.16 2.151 41.04 30.249 ;
    LAYER M2 ;
     RECT  0.031 26.766 0.103 26.784 ;
     RECT  0.103 17.892 0.175 17.91 ;
     RECT  0.031 28.962 0.175 28.98 ;
     RECT  0.103 8.631 0.203 8.649 ;
     RECT  0.103 9.486 0.203 9.504 ;
     RECT  0.103 26.532 0.247 27.36 ;
     RECT  0.175 28.422 0.247 28.98 ;
     RECT  0.247 26.532 0.347 28.98 ;
     RECT  0.103 3.852 0.535 3.87 ;
     RECT  0.499 16.11 0.535 16.128 ;
     RECT  0.175 17.388 0.535 17.91 ;
     RECT  0.031 22.716 0.535 23.04 ;
     RECT  0.535 22.59 1.723 23.04 ;
     RECT  0.535 3.312 2.16 5.634 ;
     RECT  0.103 7.092 2.16 7.11 ;
     RECT  0.535 9.594 2.16 9.612 ;
     RECT  0.535 10.71 2.16 10.728 ;
     RECT  0.103 14.652 2.16 14.67 ;
     RECT  0.535 16.11 2.16 16.398 ;
     RECT  0.535 17.388 2.16 17.982 ;
     RECT  1.723 22.212 2.16 23.04 ;
     RECT  1.147 25.182 2.16 25.2 ;
     RECT  0.347 26.532 2.16 26.55 ;
     RECT  0.347 27.342 2.16 28.98 ;
     RECT  26.635 32.346 26.987 32.364 ;
     RECT  2.16 2.151 41.04 30.249 ;
     RECT  41.04 12.366 41.567 17.064 ;
     RECT  41.567 12.366 41.603 16.974 ;
     RECT  41.04 6.588 41.639 10.584 ;
     RECT  41.603 12.366 41.639 16.794 ;
     RECT  41.04 19.746 41.675 23.004 ;
     RECT  41.639 12.996 42.143 16.794 ;
     RECT  41.04 25.326 42.143 29.754 ;
     RECT  41.639 6.822 42.179 10.584 ;
     RECT  42.143 12.996 42.179 13.896 ;
     RECT  42.143 14.652 42.179 16.794 ;
     RECT  41.675 19.926 42.179 23.004 ;
     RECT  42.143 26.064 42.179 28.674 ;
     RECT  42.179 6.822 42.215 7.992 ;
     RECT  42.179 9.126 42.215 9.612 ;
     RECT  42.179 13.536 42.215 13.554 ;
     RECT  42.179 14.796 42.215 15.246 ;
     RECT  42.179 20.7 42.215 23.004 ;
     RECT  42.215 20.736 42.251 22.23 ;
     RECT  42.215 6.822 43.115 7.416 ;
     RECT  42.215 9.126 43.115 9.342 ;
     RECT  42.179 10.566 43.115 10.584 ;
     RECT  42.215 15.066 43.115 15.084 ;
     RECT  42.251 20.736 43.115 21.834 ;
     RECT  42.215 22.986 43.115 23.004 ;
     RECT  42.179 26.766 43.115 26.784 ;
     RECT  42.143 29.736 43.115 29.754 ;
    LAYER M3 ;
     RECT  37.515 2.143 37.605 2.227 ;
     RECT  29.415 2.143 29.505 2.299 ;
     RECT  37.188 2.227 37.605 2.299 ;
     RECT  29.088 2.299 30.042 2.371 ;
     RECT  36.54 2.299 37.605 2.371 ;
     RECT  2.415 2.143 2.505 2.413 ;
     RECT  5.115 2.143 5.205 2.413 ;
     RECT  7.815 2.143 7.905 2.413 ;
     RECT  10.515 2.143 10.605 2.413 ;
     RECT  13.215 2.143 13.305 2.413 ;
     RECT  15.915 2.143 16.005 2.413 ;
     RECT  18.615 2.143 18.705 2.413 ;
     RECT  21.315 2.143 21.405 2.413 ;
     RECT  24.015 2.143 24.105 2.413 ;
     RECT  26.715 2.143 26.805 2.413 ;
     RECT  32.115 2.143 32.205 2.413 ;
     RECT  34.815 2.143 34.905 2.413 ;
     RECT  40.215 2.143 40.305 2.413 ;
     RECT  36.54 2.371 37.962 2.533 ;
     RECT  32.115 2.413 32.397 2.569 ;
     RECT  38.736 2.497 38.754 2.569 ;
     RECT  38.736 2.569 39.15 2.597 ;
     RECT  34.815 2.413 35.097 2.605 ;
     RECT  36.396 2.533 37.962 2.605 ;
     RECT  26.715 2.413 26.997 2.641 ;
     RECT  31.932 2.569 32.397 2.641 ;
     RECT  34.236 2.605 35.097 2.641 ;
     RECT  36.252 2.605 37.962 2.641 ;
     RECT  28.98 2.371 30.258 2.731 ;
     RECT  26.715 2.641 28.062 2.767 ;
     RECT  28.98 2.731 30.51 2.767 ;
     RECT  31.752 2.641 32.562 2.767 ;
     RECT  34.236 2.641 35.154 2.803 ;
     RECT  36.144 2.641 37.962 2.803 ;
     RECT  31.752 2.767 33.102 2.827 ;
     RECT  34.236 2.803 37.962 2.831 ;
     RECT  31.752 2.827 33.318 2.875 ;
     RECT  24.015 2.413 24.297 2.911 ;
     RECT  31.32 2.875 33.318 2.911 ;
     RECT  34.236 2.831 35.658 2.911 ;
     RECT  26.715 2.767 30.51 3.037 ;
     RECT  31.32 2.911 35.658 3.037 ;
     RECT  26.715 3.037 35.658 3.181 ;
     RECT  26.172 3.181 35.658 3.299 ;
     RECT  2.415 2.413 2.697 3.307 ;
     RECT  36.432 2.831 37.962 3.307 ;
     RECT  36.432 3.307 38.178 3.343 ;
     RECT  28.944 3.299 30.474 3.371 ;
     RECT  26.172 3.299 28.206 3.541 ;
     RECT  21.315 2.413 21.597 3.595 ;
     RECT  15.048 3.403 15.066 3.605 ;
     RECT  21.315 3.595 22.23 3.649 ;
     RECT  36.432 3.343 38.214 3.649 ;
     RECT  2.376 3.307 2.697 3.691 ;
     RECT  23.652 2.911 24.297 3.721 ;
     RECT  36.432 3.649 38.358 3.721 ;
     RECT  0.54 3.307 0.558 3.787 ;
     RECT  25.956 3.541 28.206 3.811 ;
     RECT  0.108 3.787 0.558 3.875 ;
     RECT  36.432 3.721 38.394 3.883 ;
     RECT  39.132 2.597 39.15 3.883 ;
     RECT  23.652 3.721 24.678 3.931 ;
     RECT  5.115 2.413 5.397 3.979 ;
     RECT  23.4 3.931 24.678 3.991 ;
     RECT  25.416 3.811 28.206 3.991 ;
     RECT  36.432 3.883 39.15 3.991 ;
     RECT  5.115 3.979 5.49 4.019 ;
     RECT  21.315 3.649 22.374 4.117 ;
     RECT  23.4 3.991 28.206 4.117 ;
     RECT  28.944 3.371 30.222 4.117 ;
     RECT  31.284 3.299 35.658 4.117 ;
     RECT  2.304 3.691 2.697 4.219 ;
     RECT  14.832 3.979 14.85 4.261 ;
     RECT  21.315 4.117 28.206 4.261 ;
     RECT  28.944 4.117 35.658 4.261 ;
     RECT  36.396 3.991 39.15 4.261 ;
     RECT  5.115 4.019 5.397 4.351 ;
     RECT  13.215 2.413 13.497 4.351 ;
     RECT  14.256 4.261 14.85 4.379 ;
     RECT  10.515 2.413 10.797 4.387 ;
     RECT  13.104 4.351 13.497 4.397 ;
     RECT  21.315 4.261 39.15 4.451 ;
     RECT  18.615 2.413 18.897 4.459 ;
     RECT  5.04 4.351 5.397 4.493 ;
     RECT  6.84 4.363 6.858 4.493 ;
     RECT  14.832 4.379 14.85 4.493 ;
     RECT  21.315 4.451 22.626 4.495 ;
     RECT  10.515 4.387 10.854 4.523 ;
     RECT  40.215 2.413 40.497 4.693 ;
     RECT  23.364 4.451 39.15 4.765 ;
     RECT  39.96 4.693 40.497 4.765 ;
     RECT  18.324 4.459 18.897 4.801 ;
     RECT  0.144 3.875 0.558 4.843 ;
     RECT  20.988 4.495 22.626 4.963 ;
     RECT  18.324 4.801 19.098 5.071 ;
     RECT  18.216 5.071 19.098 5.197 ;
     RECT  20.448 4.963 22.626 5.197 ;
     RECT  2.304 4.219 2.754 5.225 ;
     RECT  13.215 4.397 13.497 5.275 ;
     RECT  6.444 4.651 6.462 5.305 ;
     RECT  9.108 5.161 9.126 5.341 ;
     RECT  18.216 5.197 19.17 5.341 ;
     RECT  19.98 5.197 22.626 5.341 ;
     RECT  5.115 4.493 5.397 5.467 ;
     RECT  6.444 5.305 6.678 5.495 ;
     RECT  15.915 2.413 16.197 5.515 ;
     RECT  12.456 5.575 12.474 5.611 ;
     RECT  13.215 5.275 13.986 5.611 ;
     RECT  18.216 5.341 22.626 5.707 ;
     RECT  23.364 4.765 40.497 5.707 ;
     RECT  0.108 4.843 0.558 5.741 ;
     RECT  18.216 5.707 40.497 5.765 ;
     RECT  5.115 5.467 5.598 5.773 ;
     RECT  12.456 5.611 13.986 5.773 ;
     RECT  14.94 5.737 14.958 5.773 ;
     RECT  3.672 5.701 4.014 5.801 ;
     RECT  18.216 5.765 19.494 5.845 ;
     RECT  20.268 5.765 40.497 5.845 ;
     RECT  2.34 5.225 2.754 5.873 ;
     RECT  3.996 5.801 4.014 5.873 ;
     RECT  6.48 5.495 6.678 5.881 ;
     RECT  7.815 2.413 8.097 5.881 ;
     RECT  9.108 5.341 9.198 5.881 ;
     RECT  14.94 5.773 15.138 5.881 ;
     RECT  15.915 5.515 16.254 5.881 ;
     RECT  20.268 5.845 40.554 5.881 ;
     RECT  14.94 5.881 16.254 5.995 ;
     RECT  17.496 5.845 19.494 5.999 ;
     RECT  6.48 5.881 8.097 6.007 ;
     RECT  2.376 5.873 2.754 6.043 ;
     RECT  10.515 4.523 10.797 6.043 ;
     RECT  10.515 6.043 10.854 6.115 ;
     RECT  6.48 6.007 8.262 6.151 ;
     RECT  9.108 5.881 9.342 6.151 ;
     RECT  10.296 6.115 10.854 6.151 ;
     RECT  14.94 5.995 16.542 6.151 ;
     RECT  17.496 5.999 19.386 6.151 ;
     RECT  2.376 6.043 2.79 6.173 ;
     RECT  6.48 6.151 9.342 6.277 ;
     RECT  10.296 6.151 11.178 6.277 ;
     RECT  11.952 5.773 13.986 6.277 ;
     RECT  5.115 5.773 5.67 6.283 ;
     RECT  6.408 6.277 9.342 6.283 ;
     RECT  10.08 6.277 13.986 6.283 ;
     RECT  14.94 6.151 19.386 6.313 ;
     RECT  5.115 6.283 13.986 6.385 ;
     RECT  14.832 6.313 19.386 6.385 ;
     RECT  20.268 5.881 40.734 6.575 ;
     RECT  0.108 5.741 0.198 6.605 ;
     RECT  26.676 6.575 40.734 6.611 ;
     RECT  26.715 6.611 40.734 6.619 ;
     RECT  41.616 6.583 41.634 6.619 ;
     RECT  5.115 6.385 19.386 6.859 ;
     RECT  20.268 6.575 25.866 6.859 ;
     RECT  5.115 6.859 25.866 6.989 ;
     RECT  15.876 6.989 25.866 7.079 ;
     RECT  0.108 6.605 0.126 7.115 ;
     RECT  26.715 6.619 41.634 7.147 ;
     RECT  26.715 7.147 42.174 7.151 ;
     RECT  4.032 5.995 4.05 7.159 ;
     RECT  39.276 7.151 42.174 7.321 ;
     RECT  3.852 7.159 4.05 7.349 ;
     RECT  5.115 6.989 15.138 7.349 ;
     RECT  15.915 7.079 25.866 7.349 ;
     RECT  2.376 6.173 2.697 7.385 ;
     RECT  15.915 7.349 22.086 7.421 ;
     RECT  43.092 6.817 43.11 7.469 ;
     RECT  15.915 7.421 21.87 7.493 ;
     RECT  4.032 7.349 4.05 7.627 ;
     RECT  4.032 7.627 4.23 7.655 ;
     RECT  22.824 7.349 25.866 7.655 ;
     RECT  22.86 7.655 25.866 7.735 ;
     RECT  26.715 7.151 38.466 7.735 ;
     RECT  4.212 7.655 4.23 7.799 ;
     RECT  22.86 7.735 38.466 7.889 ;
     RECT  39.276 7.321 42.21 7.897 ;
     RECT  9.144 7.349 15.138 7.925 ;
     RECT  13.176 7.925 15.138 7.933 ;
     RECT  15.915 7.493 21.726 7.933 ;
     RECT  26.715 7.889 38.466 8.005 ;
     RECT  39.204 7.897 42.21 8.005 ;
     RECT  22.86 7.889 25.938 8.069 ;
     RECT  5.115 7.349 8.334 8.131 ;
     RECT  9.144 7.925 12.33 8.131 ;
     RECT  22.86 8.069 25.758 8.159 ;
     RECT  22.86 8.159 25.686 8.195 ;
     RECT  5.115 8.131 12.33 8.267 ;
     RECT  13.176 7.933 21.726 8.275 ;
     RECT  5.115 8.267 5.397 8.491 ;
     RECT  6.948 8.267 12.33 8.525 ;
     RECT  13.176 8.275 22.05 8.581 ;
     RECT  22.86 8.195 25.578 8.581 ;
     RECT  6.948 8.525 8.478 8.609 ;
     RECT  13.176 8.581 25.578 8.699 ;
     RECT  0.108 8.62 0.198 8.717 ;
     RECT  26.715 8.005 42.21 8.717 ;
     RECT  17.604 8.699 25.578 8.807 ;
     RECT  9.36 8.525 12.33 8.815 ;
     RECT  9.36 8.815 12.402 8.851 ;
     RECT  2.415 7.385 2.697 8.875 ;
     RECT  9.36 8.851 12.438 9.112 ;
     RECT  13.176 8.699 16.866 9.112 ;
     RECT  2.304 8.875 2.697 9.115 ;
     RECT  26.715 8.717 40.698 9.121 ;
     RECT  26.496 9.121 40.698 9.211 ;
     RECT  17.964 8.807 25.578 9.247 ;
     RECT  26.352 9.211 40.698 9.247 ;
     RECT  6.948 8.609 8.442 9.259 ;
     RECT  0.144 8.717 0.198 9.451 ;
     RECT  6.876 9.259 8.442 9.451 ;
     RECT  0.108 9.451 0.198 9.509 ;
     RECT  6.876 9.451 8.478 9.547 ;
     RECT  2.304 9.115 2.754 9.581 ;
     RECT  0.144 9.509 0.198 9.589 ;
     RECT  9.36 9.112 16.866 9.589 ;
     RECT  17.964 9.247 40.698 9.589 ;
     RECT  41.544 8.717 42.21 9.617 ;
     RECT  6.84 9.547 8.478 9.661 ;
     RECT  9.324 9.589 40.698 9.661 ;
     RECT  2.304 9.581 2.697 9.689 ;
     RECT  6.84 9.661 40.698 9.787 ;
     RECT  4.788 8.491 5.397 9.823 ;
     RECT  6.264 9.787 40.698 9.823 ;
     RECT  41.544 9.617 42.174 9.887 ;
     RECT  0.144 9.589 0.558 9.917 ;
     RECT  4.788 9.823 40.698 9.959 ;
     RECT  4.788 9.959 40.497 10.049 ;
     RECT  42.12 9.887 42.174 10.049 ;
     RECT  0.216 9.917 0.558 10.205 ;
     RECT  4.788 10.049 39.078 10.205 ;
     RECT  0.288 10.205 0.558 10.253 ;
     RECT  42.156 10.049 42.174 10.319 ;
     RECT  43.092 8.971 43.11 10.589 ;
     RECT  4.788 10.205 28.602 10.733 ;
     RECT  2.415 9.689 2.697 10.795 ;
     RECT  2.304 10.795 2.697 10.831 ;
     RECT  3.6 9.121 3.618 10.831 ;
     RECT  20.232 10.733 28.602 10.859 ;
     RECT  0.54 10.253 0.558 10.925 ;
     RECT  29.34 10.205 39.078 10.931 ;
     RECT  31.5 10.931 39.078 11.011 ;
     RECT  20.484 10.859 28.602 11.101 ;
     RECT  29.34 10.931 30.69 11.101 ;
     RECT  4.788 10.733 19.386 11.165 ;
     RECT  2.304 10.831 3.618 11.309 ;
     RECT  0.144 11.083 0.27 11.371 ;
     RECT  9.18 11.165 19.386 11.399 ;
     RECT  4.788 11.165 8.37 11.435 ;
     RECT  31.5 11.011 39.114 11.551 ;
     RECT  20.484 11.101 30.69 11.677 ;
     RECT  2.34 11.309 3.618 11.693 ;
     RECT  20.412 11.677 30.69 11.707 ;
     RECT  31.5 11.551 39.186 11.707 ;
     RECT  20.412 11.707 39.186 11.749 ;
     RECT  2.415 11.693 3.618 11.755 ;
     RECT  20.412 11.749 39.402 11.821 ;
     RECT  40.215 10.049 40.497 11.821 ;
     RECT  0.108 11.371 0.27 11.885 ;
     RECT  9.18 11.399 13.497 12.011 ;
     RECT  14.256 11.399 19.386 12.091 ;
     RECT  20.412 11.821 40.497 12.091 ;
     RECT  12.78 12.011 13.497 12.187 ;
     RECT  14.256 12.091 40.497 12.187 ;
     RECT  2.415 11.755 3.726 12.235 ;
     RECT  2.415 12.235 4.194 12.289 ;
     RECT  4.968 11.435 8.37 12.289 ;
     RECT  9.18 12.011 11.97 12.427 ;
     RECT  0.108 11.885 0.162 12.461 ;
     RECT  2.415 12.289 8.37 12.515 ;
     RECT  12.78 12.187 40.497 12.721 ;
     RECT  41.616 12.361 41.634 12.721 ;
     RECT  12.78 12.721 41.634 12.857 ;
     RECT  4.572 12.515 8.37 12.991 ;
     RECT  9.108 12.427 11.97 12.991 ;
     RECT  23.472 12.857 41.634 12.991 ;
     RECT  4.572 12.991 11.97 13.063 ;
     RECT  12.78 12.857 22.734 13.063 ;
     RECT  4.572 13.063 22.734 13.085 ;
     RECT  6.228 13.085 19.098 13.433 ;
     RECT  3.6 12.515 3.726 13.441 ;
     RECT  4.572 13.085 5.397 13.441 ;
     RECT  23.472 12.991 42.174 13.531 ;
     RECT  6.228 13.433 19.062 13.595 ;
     RECT  14.616 13.595 19.062 13.667 ;
     RECT  20.052 13.085 22.734 13.675 ;
     RECT  23.472 13.531 42.21 13.675 ;
     RECT  20.052 13.675 42.21 13.805 ;
     RECT  3.6 13.441 5.397 13.837 ;
     RECT  20.052 13.805 42.174 13.865 ;
     RECT  20.304 13.865 42.174 13.973 ;
     RECT  3.6 13.837 5.454 13.981 ;
     RECT  6.228 13.595 13.662 13.981 ;
     RECT  20.556 13.973 42.174 13.997 ;
     RECT  20.556 13.997 40.497 14.045 ;
     RECT  3.6 13.981 13.662 14.135 ;
     RECT  4.464 14.135 13.662 14.141 ;
     RECT  14.724 13.667 19.062 14.179 ;
     RECT  14.724 14.179 19.098 14.215 ;
     RECT  20.556 14.045 22.662 14.243 ;
     RECT  23.724 14.045 40.497 14.369 ;
     RECT  20.556 14.243 22.59 14.405 ;
     RECT  41.508 13.997 42.174 14.549 ;
     RECT  0.108 12.461 0.126 14.675 ;
     RECT  41.544 14.549 42.174 14.731 ;
     RECT  41.544 14.731 42.21 14.747 ;
     RECT  20.556 14.405 21.597 14.791 ;
     RECT  14.724 14.215 19.134 14.827 ;
     RECT  20.484 14.791 21.597 14.827 ;
     RECT  4.572 14.141 13.662 14.917 ;
     RECT  14.724 14.827 21.597 14.917 ;
     RECT  23.724 14.369 38.178 14.917 ;
     RECT  4.572 14.917 21.597 14.945 ;
     RECT  38.988 14.369 40.497 15.025 ;
     RECT  22.356 14.405 22.59 15.061 ;
     RECT  23.58 14.917 38.178 15.061 ;
     RECT  43.092 15.061 43.11 15.149 ;
     RECT  22.356 15.061 38.178 15.151 ;
     RECT  38.988 15.025 40.554 15.151 ;
     RECT  4.572 14.945 16.686 15.179 ;
     RECT  22.356 15.151 40.554 15.215 ;
     RECT  41.58 14.747 42.21 15.251 ;
     RECT  25.884 15.215 40.554 15.359 ;
     RECT  33.948 15.359 40.554 15.421 ;
     RECT  4.572 15.179 12.402 15.485 ;
     RECT  33.948 15.421 40.626 15.491 ;
     RECT  17.532 14.945 21.597 15.493 ;
     RECT  22.356 15.215 25.002 15.493 ;
     RECT  41.58 15.251 42.174 15.529 ;
     RECT  34.236 15.491 40.626 15.557 ;
     RECT  17.532 15.493 25.002 15.677 ;
     RECT  13.14 15.179 16.686 15.691 ;
     RECT  17.532 15.677 19.026 15.691 ;
     RECT  2.415 12.515 2.697 15.799 ;
     RECT  3.6 14.135 3.618 15.799 ;
     RECT  19.8 15.677 25.002 15.979 ;
     RECT  25.884 15.359 33.21 15.979 ;
     RECT  19.8 15.979 33.21 15.989 ;
     RECT  19.8 15.989 29.862 16.025 ;
     RECT  0.108 16.075 0.126 16.105 ;
     RECT  5.076 15.485 12.402 16.105 ;
     RECT  13.14 15.691 19.026 16.105 ;
     RECT  5.076 16.105 19.026 16.267 ;
     RECT  4.716 16.267 19.026 16.367 ;
     RECT  0.108 16.105 0.522 16.375 ;
     RECT  0.108 16.375 0.558 16.397 ;
     RECT  19.8 16.025 29.826 16.397 ;
     RECT  34.236 15.557 40.59 16.411 ;
     RECT  34.092 16.411 40.59 16.529 ;
     RECT  34.092 16.529 36.486 16.537 ;
     RECT  7.272 16.367 19.026 16.603 ;
     RECT  19.8 16.397 27.774 16.603 ;
     RECT  37.26 16.529 40.59 16.609 ;
     RECT  41.544 15.529 42.174 16.609 ;
     RECT  2.415 15.799 3.618 16.645 ;
     RECT  30.636 15.989 33.21 16.681 ;
     RECT  33.948 16.537 36.486 16.681 ;
     RECT  0.144 16.397 0.558 16.685 ;
     RECT  37.26 16.609 42.174 16.709 ;
     RECT  28.548 16.397 29.826 16.771 ;
     RECT  30.636 16.681 36.486 16.771 ;
     RECT  0.144 16.685 0.522 16.781 ;
     RECT  41.508 16.709 42.174 16.781 ;
     RECT  41.544 16.781 42.174 16.799 ;
     RECT  28.548 16.771 36.486 16.835 ;
     RECT  2.376 16.645 3.618 16.843 ;
     RECT  37.26 16.709 40.59 16.907 ;
     RECT  7.272 16.603 27.774 16.943 ;
     RECT  41.544 16.799 41.598 16.979 ;
     RECT  0.144 16.781 0.342 17.069 ;
     RECT  41.544 16.979 41.562 17.069 ;
     RECT  2.376 16.843 3.978 17.077 ;
     RECT  4.716 16.367 6.498 17.077 ;
     RECT  2.376 17.077 6.498 17.149 ;
     RECT  7.272 16.943 22.05 17.149 ;
     RECT  2.376 17.149 22.05 17.221 ;
     RECT  2.268 17.221 22.05 17.261 ;
     RECT  28.584 16.835 36.486 17.419 ;
     RECT  37.26 16.907 40.497 17.419 ;
     RECT  23.04 16.943 27.774 17.581 ;
     RECT  23.04 17.581 27.846 17.617 ;
     RECT  28.584 17.419 40.497 17.617 ;
     RECT  0.18 17.069 0.342 17.653 ;
     RECT  2.304 17.261 22.05 17.689 ;
     RECT  2.304 17.689 22.23 17.851 ;
     RECT  23.04 17.617 40.497 17.851 ;
     RECT  0.18 17.653 0.558 17.887 ;
     RECT  2.304 17.851 40.497 17.987 ;
     RECT  2.304 17.987 39.33 18.149 ;
     RECT  22.824 18.149 39.33 18.185 ;
     RECT  2.304 18.149 22.05 18.257 ;
     RECT  0.108 17.887 0.558 18.317 ;
     RECT  31.032 18.185 39.33 18.805 ;
     RECT  0.108 18.317 0.342 18.989 ;
     RECT  22.824 18.185 30.294 19.003 ;
     RECT  22.788 19.003 30.294 19.051 ;
     RECT  31.032 18.805 39.366 19.051 ;
     RECT  2.304 18.257 21.978 19.075 ;
     RECT  22.788 19.051 39.366 19.139 ;
     RECT  2.304 19.075 22.05 19.243 ;
     RECT  22.788 19.139 33.678 19.277 ;
     RECT  0.108 18.989 0.162 19.325 ;
     RECT  22.788 19.277 33.426 19.325 ;
     RECT  34.416 19.139 39.366 19.325 ;
     RECT  34.488 19.325 39.366 19.373 ;
     RECT  32.115 19.325 33.426 19.499 ;
     RECT  34.488 19.373 36.594 19.499 ;
     RECT  32.115 19.499 33.318 19.535 ;
     RECT  1.728 19.243 22.05 19.543 ;
     RECT  22.788 19.325 31.302 19.543 ;
     RECT  32.115 19.535 33.246 19.571 ;
     RECT  40.215 17.987 40.497 19.777 ;
     RECT  37.332 19.373 39.366 19.885 ;
     RECT  40.176 19.777 40.497 19.885 ;
     RECT  41.652 19.741 41.67 19.912 ;
     RECT  32.115 19.571 33.138 19.949 ;
     RECT  41.652 19.912 42.174 20.011 ;
     RECT  34.488 19.499 36.522 20.039 ;
     RECT  37.332 19.885 40.497 20.039 ;
     RECT  38.52 20.039 40.497 20.107 ;
     RECT  41.58 20.011 42.174 20.107 ;
     RECT  1.728 19.543 31.302 20.119 ;
     RECT  32.115 19.949 32.454 20.119 ;
     RECT  1.728 20.119 32.454 20.381 ;
     RECT  36.432 20.039 36.522 20.461 ;
     RECT  37.332 20.039 37.797 20.461 ;
     RECT  38.52 20.107 42.174 20.578 ;
     RECT  38.52 20.578 42.21 20.723 ;
     RECT  36.432 20.461 37.797 20.821 ;
     RECT  38.52 20.723 42.174 20.821 ;
     RECT  33.192 20.821 33.21 20.923 ;
     RECT  1.728 20.381 32.397 20.957 ;
     RECT  34.488 20.039 35.622 20.965 ;
     RECT  1.728 20.957 10.926 20.993 ;
     RECT  36.432 20.821 42.174 21.005 ;
     RECT  11.736 20.957 32.397 21.029 ;
     RECT  33.192 20.923 33.498 21.091 ;
     RECT  34.344 20.965 35.622 21.091 ;
     RECT  11.952 21.029 32.397 21.119 ;
     RECT  12.168 21.119 32.397 21.211 ;
     RECT  12.168 21.211 32.454 21.235 ;
     RECT  33.192 21.091 35.622 21.235 ;
     RECT  12.168 21.235 35.622 21.263 ;
     RECT  19.62 21.263 35.622 21.271 ;
     RECT  36.432 21.005 40.497 21.271 ;
     RECT  19.62 21.271 40.497 21.389 ;
     RECT  19.62 21.389 33.462 21.659 ;
     RECT  34.452 21.389 40.497 21.659 ;
     RECT  1.728 20.993 10.797 21.811 ;
     RECT  43.092 20.731 43.11 21.839 ;
     RECT  1.728 21.811 10.926 21.901 ;
     RECT  12.168 21.263 18.897 21.901 ;
     RECT  19.62 21.659 33.066 21.971 ;
     RECT  1.728 21.901 18.897 22.001 ;
     RECT  41.58 21.005 42.174 22.027 ;
     RECT  1.728 22.001 10.854 22.109 ;
     RECT  41.58 22.027 42.21 22.123 ;
     RECT  11.592 22.001 18.897 22.207 ;
     RECT  19.62 21.971 33.03 22.207 ;
     RECT  1.728 22.109 10.797 22.235 ;
     RECT  11.592 22.207 33.03 22.235 ;
     RECT  41.58 22.123 42.246 22.235 ;
     RECT  41.58 22.235 42.21 22.253 ;
     RECT  36.216 21.659 40.497 22.279 ;
     RECT  34.452 21.659 35.478 22.441 ;
     RECT  36.216 22.279 41.058 22.541 ;
     RECT  0.108 19.325 0.126 22.555 ;
     RECT  0.108 22.555 0.162 22.585 ;
     RECT  34.272 22.441 35.478 22.585 ;
     RECT  42.12 22.253 42.21 22.613 ;
     RECT  42.12 22.613 42.174 22.649 ;
     RECT  0.108 22.585 0.558 22.711 ;
     RECT  34.056 22.585 35.478 22.711 ;
     RECT  36.216 22.541 37.797 22.711 ;
     RECT  38.736 22.541 41.058 22.739 ;
     RECT  42.12 22.649 42.138 22.739 ;
     RECT  34.056 22.711 37.797 22.747 ;
     RECT  0.036 22.711 0.558 22.795 ;
     RECT  40.215 22.739 41.058 22.829 ;
     RECT  0.036 22.795 1.17 22.925 ;
     RECT  43.092 22.891 43.11 23.009 ;
     RECT  0.036 22.925 0.342 23.045 ;
     RECT  33.3 22.747 37.797 23.089 ;
     RECT  38.736 22.739 39.258 23.279 ;
     RECT  40.215 22.829 40.554 23.279 ;
     RECT  2.304 22.235 10.797 23.315 ;
     RECT  38.736 23.279 38.862 23.315 ;
     RECT  12.528 22.235 32.397 23.323 ;
     RECT  33.156 23.089 37.797 23.323 ;
     RECT  11.592 22.235 11.61 23.395 ;
     RECT  12.528 23.323 38.394 23.395 ;
     RECT  10.515 23.315 10.797 23.659 ;
     RECT  11.592 23.395 38.394 23.659 ;
     RECT  10.515 23.659 38.394 23.819 ;
     RECT  0.324 23.045 0.342 23.851 ;
     RECT  0.108 23.851 0.342 23.885 ;
     RECT  17.964 23.819 38.394 23.933 ;
     RECT  10.515 23.819 17.154 24.089 ;
     RECT  2.304 23.315 9.666 24.097 ;
     RECT  1.152 22.925 1.17 24.187 ;
     RECT  14.364 24.089 17.154 24.233 ;
     RECT  14.436 24.233 17.154 24.317 ;
     RECT  1.152 24.187 1.206 24.331 ;
     RECT  18.432 23.933 38.394 24.431 ;
     RECT  30.708 24.431 38.394 24.439 ;
     RECT  1.152 24.331 1.314 24.461 ;
     RECT  30.708 24.439 38.97 24.467 ;
     RECT  2.304 24.097 9.738 24.475 ;
     RECT  10.515 24.089 13.497 24.475 ;
     RECT  30.744 24.467 38.97 24.503 ;
     RECT  0.108 23.885 0.162 24.619 ;
     RECT  18.432 24.431 29.862 24.943 ;
     RECT  2.304 24.475 13.497 25.007 ;
     RECT  5.115 25.007 13.497 25.043 ;
     RECT  8.964 25.043 13.497 25.051 ;
     RECT  14.436 24.317 17.118 25.051 ;
     RECT  18.216 24.943 29.862 25.051 ;
     RECT  5.115 25.043 8.154 25.079 ;
     RECT  1.152 24.461 1.17 25.205 ;
     RECT  2.304 25.007 4.194 25.205 ;
     RECT  18.144 25.051 29.862 25.285 ;
     RECT  30.78 24.503 38.97 25.285 ;
     RECT  8.964 25.051 17.118 25.349 ;
     RECT  2.304 25.205 4.05 25.387 ;
     RECT  15.768 25.349 17.118 25.579 ;
     RECT  40.215 23.279 40.497 25.591 ;
     RECT  15.768 25.579 17.262 25.771 ;
     RECT  6.444 25.079 8.154 25.816 ;
     RECT  2.232 25.387 4.05 25.817 ;
     RECT  18.144 25.285 39.33 25.825 ;
     RECT  40.215 25.591 40.554 25.825 ;
     RECT  6.3 25.816 8.154 25.853 ;
     RECT  42.12 25.321 42.138 25.861 ;
     RECT  6.84 25.853 8.154 25.987 ;
     RECT  8.964 25.349 14.922 25.987 ;
     RECT  15.768 25.771 17.334 26.023 ;
     RECT  18.144 25.825 40.554 26.023 ;
     RECT  41.616 25.861 42.138 26.059 ;
     RECT  2.232 25.817 3.69 26.087 ;
     RECT  6.84 25.987 14.922 26.293 ;
     RECT  15.768 26.023 40.554 26.293 ;
     RECT  5.115 25.079 5.397 26.401 ;
     RECT  2.304 26.087 3.69 26.671 ;
     RECT  4.428 26.401 5.397 26.671 ;
     RECT  0.108 24.619 0.342 26.761 ;
     RECT  6.84 26.293 40.554 26.779 ;
     RECT  41.616 26.059 42.174 26.779 ;
     RECT  0.036 26.761 0.342 26.789 ;
     RECT  43.092 26.761 43.11 26.861 ;
     RECT  2.304 26.671 5.397 26.969 ;
     RECT  2.304 26.969 3.294 27.095 ;
     RECT  6.84 26.779 42.174 27.293 ;
     RECT  6.84 27.293 32.397 27.677 ;
     RECT  6.84 27.677 24.606 27.707 ;
     RECT  33.12 27.293 42.174 27.707 ;
     RECT  6.84 27.707 8.946 27.739 ;
     RECT  4.428 26.969 5.397 27.751 ;
     RECT  12.168 27.707 24.606 27.773 ;
     RECT  0.036 26.789 0.27 27.779 ;
     RECT  38.844 27.707 42.174 27.821 ;
     RECT  33.12 27.707 38.07 27.869 ;
     RECT  2.415 27.095 3.294 27.905 ;
     RECT  9.684 27.707 11.43 27.905 ;
     RECT  33.192 27.869 38.07 27.905 ;
     RECT  4.248 27.751 5.397 27.917 ;
     RECT  6.804 27.739 8.946 27.917 ;
     RECT  7.524 27.917 8.946 27.965 ;
     RECT  12.168 27.773 20.25 28.013 ;
     RECT  25.344 27.677 32.397 28.021 ;
     RECT  21.024 27.773 24.606 28.049 ;
     RECT  38.844 27.821 40.554 28.049 ;
     RECT  7.815 27.965 8.946 28.139 ;
     RECT  25.344 28.021 32.418 28.139 ;
     RECT  12.168 28.013 13.842 28.175 ;
     RECT  10.188 27.905 11.43 28.247 ;
     RECT  21.096 28.049 24.606 28.408 ;
     RECT  25.344 28.139 32.397 28.408 ;
     RECT  3.636 28.291 4.086 28.409 ;
     RECT  7.815 28.139 8.622 28.409 ;
     RECT  10.188 28.247 11.142 28.409 ;
     RECT  12.204 28.175 13.842 28.409 ;
     RECT  0.036 27.779 0.198 28.445 ;
     RECT  10.188 28.409 10.854 28.445 ;
     RECT  7.815 28.409 8.586 28.481 ;
     RECT  38.844 28.049 40.497 28.489 ;
     RECT  33.444 27.905 38.07 28.651 ;
     RECT  38.808 28.489 40.497 28.651 ;
     RECT  12.888 28.409 13.842 28.679 ;
     RECT  33.444 28.651 40.497 28.679 ;
     RECT  41.58 27.821 42.174 28.688 ;
     RECT  12.888 28.679 13.806 28.715 ;
     RECT  33.444 28.679 39.006 28.751 ;
     RECT  14.832 28.013 20.25 28.795 ;
     RECT  21.096 28.408 32.397 28.795 ;
     RECT  33.444 28.751 37.797 28.831 ;
     RECT  10.515 28.445 10.854 28.859 ;
     RECT  38.52 28.751 39.006 28.859 ;
     RECT  41.58 28.688 42.138 28.939 ;
     RECT  4.068 28.409 4.086 28.949 ;
     RECT  14.616 28.795 32.397 28.973 ;
     RECT  0.036 28.445 0.054 28.985 ;
     RECT  13.14 28.715 13.806 28.985 ;
     RECT  14.868 28.973 32.397 29.021 ;
     RECT  14.94 29.021 32.397 29.057 ;
     RECT  14.94 29.057 29.754 29.093 ;
     RECT  30.816 29.057 32.397 29.101 ;
     RECT  33.228 28.831 37.797 29.101 ;
     RECT  38.52 28.859 38.97 29.219 ;
     RECT  39.744 28.679 40.497 29.219 ;
     RECT  41.544 28.939 42.138 29.219 ;
     RECT  38.52 29.219 38.862 29.255 ;
     RECT  41.544 29.219 41.85 29.327 ;
     RECT  15.372 29.093 29.754 29.399 ;
     RECT  41.58 29.327 41.85 29.399 ;
     RECT  15.915 29.399 29.754 29.489 ;
     RECT  38.52 29.255 38.538 29.489 ;
     RECT  39.888 29.219 40.497 29.489 ;
     RECT  41.58 29.399 41.598 29.489 ;
     RECT  39.96 29.489 40.497 29.525 ;
     RECT  17.028 29.489 25.722 29.561 ;
     RECT  30.816 29.101 37.797 29.633 ;
     RECT  15.915 29.489 16.254 29.645 ;
     RECT  26.568 29.489 29.754 29.645 ;
     RECT  19.908 29.561 25.002 29.759 ;
     RECT  26.604 29.645 29.754 29.759 ;
     RECT  30.816 29.633 33.21 29.759 ;
     RECT  33.984 29.633 37.797 29.759 ;
     RECT  43.092 28.747 43.11 29.759 ;
     RECT  30.816 29.759 33.066 29.789 ;
     RECT  33.984 29.759 35.874 29.789 ;
     RECT  17.028 29.561 19.098 29.795 ;
     RECT  19.944 29.759 25.002 29.795 ;
     RECT  26.604 29.759 29.697 29.795 ;
     RECT  33.984 29.789 35.262 29.795 ;
     RECT  40.14 29.525 40.497 29.795 ;
     RECT  17.676 29.795 19.098 29.831 ;
     RECT  23.328 29.795 25.002 29.903 ;
     RECT  23.328 29.903 24.93 29.939 ;
     RECT  28.548 29.795 29.697 29.939 ;
     RECT  2.415 27.905 2.697 29.987 ;
     RECT  5.115 27.917 5.397 29.987 ;
     RECT  7.815 28.481 8.097 29.987 ;
     RECT  10.515 28.859 10.797 29.987 ;
     RECT  13.215 28.985 13.497 29.987 ;
     RECT  15.915 29.645 16.197 29.987 ;
     RECT  17.676 29.831 18.897 29.987 ;
     RECT  19.944 29.795 22.41 29.987 ;
     RECT  28.584 29.939 29.697 29.987 ;
     RECT  30.816 29.789 32.397 29.987 ;
     RECT  36.648 29.759 37.797 29.987 ;
     RECT  40.215 29.795 40.497 29.987 ;
     RECT  17.676 29.987 18.705 30.029 ;
     RECT  22.284 29.987 22.41 30.029 ;
     RECT  23.328 29.939 24.75 30.029 ;
     RECT  26.604 29.795 27.666 30.029 ;
     RECT  28.584 29.987 29.505 30.029 ;
     RECT  30.816 29.987 32.205 30.029 ;
     RECT  33.984 29.795 34.074 30.029 ;
     RECT  34.815 29.795 35.262 30.029 ;
     RECT  36.648 29.987 37.605 30.029 ;
     RECT  19.944 29.987 21.405 30.065 ;
     RECT  22.284 30.029 22.302 30.065 ;
     RECT  23.328 30.029 24.678 30.065 ;
     RECT  33.984 30.029 34.002 30.065 ;
     RECT  34.815 30.029 35.19 30.065 ;
     RECT  18.36 30.029 18.705 30.101 ;
     RECT  28.836 30.029 29.505 30.101 ;
     RECT  36.792 30.029 37.605 30.173 ;
     RECT  19.944 30.065 19.962 30.209 ;
     RECT  2.415 29.987 2.505 30.257 ;
     RECT  5.115 29.987 5.205 30.257 ;
     RECT  7.815 29.987 7.905 30.257 ;
     RECT  10.515 29.987 10.605 30.257 ;
     RECT  13.215 29.987 13.305 30.257 ;
     RECT  15.915 29.987 16.005 30.257 ;
     RECT  18.615 30.101 18.705 30.257 ;
     RECT  21.315 30.065 21.405 30.257 ;
     RECT  24.015 30.065 24.105 30.257 ;
     RECT  29.415 30.101 29.505 30.257 ;
     RECT  32.115 30.029 32.205 30.257 ;
     RECT  34.815 30.065 34.905 30.257 ;
     RECT  37.515 30.173 37.605 30.257 ;
     RECT  40.215 29.987 40.305 30.257 ;
     RECT  26.604 30.029 26.982 32.299 ;
     RECT  26.532 32.299 26.982 32.369 ;
     RECT  26.532 32.369 26.91 32.381 ;
    LAYER M4 ;
     RECT  0.06 16.368 0.097 19.368 ;
     RECT  0.06 3.312 0.169 6.312 ;
     RECT  0.06 8.496 0.173 12.456 ;
     RECT  0.169 3.312 2.408 6.6 ;
     RECT  0.173 8.496 2.408 12.36 ;
     RECT  0.097 16.08 2.408 19.368 ;
     RECT  0.06 22.512 2.408 25.512 ;
     RECT  2.408 2.148 2.512 30.252 ;
     RECT  2.512 2.418 2.704 29.982 ;
     RECT  2.704 15.984 2.981 19.368 ;
     RECT  2.981 17.136 3.341 19.368 ;
     RECT  3.341 18.816 3.629 19.368 ;
     RECT  3.629 19.296 3.769 19.368 ;
     RECT  2.704 20.496 3.769 20.52 ;
     RECT  2.704 22.08 3.949 25.32 ;
     RECT  4.093 13.632 4.453 13.656 ;
     RECT  2.981 15.984 4.705 16.104 ;
     RECT  3.341 17.136 4.705 17.736 ;
     RECT  3.769 19.296 4.813 20.52 ;
     RECT  4.813 18.816 4.885 20.52 ;
     RECT  3.949 22.032 4.885 25.8 ;
     RECT  4.705 15.984 5.065 17.736 ;
     RECT  2.704 3.408 5.108 6.6 ;
     RECT  2.704 8.496 5.108 12.36 ;
     RECT  4.453 13.632 5.108 14.136 ;
     RECT  5.065 15.84 5.108 17.736 ;
     RECT  4.885 18.816 5.108 25.8 ;
     RECT  4.417 27.072 5.108 27.912 ;
     RECT  5.108 2.148 5.212 30.252 ;
     RECT  5.212 2.418 5.404 29.982 ;
     RECT  5.404 8.736 5.699 20.04 ;
     RECT  5.699 14.352 5.897 20.04 ;
     RECT  5.897 14.928 6.083 20.04 ;
     RECT  6.083 18.048 6.397 20.04 ;
     RECT  5.404 21.12 6.397 25.848 ;
     RECT  5.699 8.736 6.685 13.176 ;
     RECT  5.404 27.072 7.045 27.912 ;
     RECT  6.685 8.736 7.225 13.56 ;
     RECT  6.397 18.048 7.297 25.848 ;
     RECT  7.045 27.024 7.513 27.912 ;
     RECT  5.404 3.408 7.808 6.6 ;
     RECT  7.225 8.496 7.808 13.56 ;
     RECT  6.083 14.928 7.808 16.584 ;
     RECT  7.297 17.616 7.808 25.848 ;
     RECT  7.513 27.024 7.808 27.96 ;
     RECT  7.808 2.148 7.912 30.252 ;
     RECT  7.912 2.418 8.104 29.982 ;
     RECT  8.104 20.736 8.561 27.768 ;
     RECT  8.104 8.16 8.579 16.344 ;
     RECT  8.579 14.832 8.921 16.344 ;
     RECT  8.921 15.456 8.993 16.344 ;
     RECT  8.561 20.976 9.065 27.768 ;
     RECT  8.993 15.504 9.313 16.344 ;
     RECT  8.104 3.408 9.349 7.176 ;
     RECT  8.579 8.16 9.349 13.704 ;
     RECT  9.349 3.408 9.685 13.704 ;
     RECT  8.104 17.952 9.709 19.368 ;
     RECT  9.313 15.504 9.733 16.968 ;
     RECT  9.709 17.952 9.733 19.896 ;
     RECT  9.065 21.12 10.177 27.768 ;
     RECT  9.685 3.408 10.213 13.8 ;
     RECT  9.733 15.504 10.213 19.896 ;
     RECT  10.213 3.408 10.319 13.896 ;
     RECT  10.319 3.408 10.357 13.944 ;
     RECT  10.213 15.456 10.357 19.896 ;
     RECT  10.357 3.408 10.508 19.896 ;
     RECT  10.177 21.12 10.508 27.912 ;
     RECT  10.508 2.148 10.612 30.252 ;
     RECT  10.612 2.418 10.804 29.982 ;
     RECT  10.804 21.984 10.973 27.912 ;
     RECT  10.804 8.736 11.441 20.808 ;
     RECT  11.441 15.984 11.585 20.808 ;
     RECT  10.804 3.408 11.869 7.704 ;
     RECT  11.441 8.736 11.909 14.52 ;
     RECT  11.585 15.984 11.945 18.216 ;
     RECT  11.945 18 12.017 18.024 ;
     RECT  11.869 3.408 12.157 7.752 ;
     RECT  11.909 8.736 12.157 14.184 ;
     RECT  10.973 24.144 12.193 27.912 ;
     RECT  11.585 19.872 12.301 20.808 ;
     RECT  10.973 21.984 12.301 23.16 ;
     RECT  12.193 24.144 12.757 28.392 ;
     RECT  12.301 19.872 13.045 23.16 ;
     RECT  12.757 24.144 13.045 28.68 ;
     RECT  13.045 19.872 13.093 28.68 ;
     RECT  12.157 3.408 13.208 14.184 ;
     RECT  11.945 15.984 13.208 16.92 ;
     RECT  13.093 19.776 13.208 28.68 ;
     RECT  13.208 2.148 13.312 30.252 ;
     RECT  13.312 2.418 13.504 29.982 ;
     RECT  13.504 3.408 13.955 27.672 ;
     RECT  13.955 13.536 14.147 27.672 ;
     RECT  14.147 13.536 14.243 18.216 ;
     RECT  14.243 13.536 14.501 16.92 ;
     RECT  14.605 28.944 14.857 28.968 ;
     RECT  14.147 19.344 15.253 27.672 ;
     RECT  14.857 28.944 15.289 29.016 ;
     RECT  14.243 18 15.577 18.216 ;
     RECT  15.253 19.344 15.577 27.72 ;
     RECT  14.501 13.536 15.685 16.824 ;
     RECT  15.577 18 15.685 27.72 ;
     RECT  13.955 3.408 15.908 12.36 ;
     RECT  15.685 13.536 15.908 27.72 ;
     RECT  15.289 28.944 15.908 29.064 ;
     RECT  15.908 2.148 16.012 30.252 ;
     RECT  16.012 2.418 16.204 29.982 ;
     RECT  16.204 15.264 16.265 17.16 ;
     RECT  16.204 28.992 16.337 29.64 ;
     RECT  16.204 3.6 16.373 14.232 ;
     RECT  16.204 18.432 16.589 28.008 ;
     RECT  16.265 15.264 16.625 16.488 ;
     RECT  16.589 18.528 16.835 28.008 ;
     RECT  16.835 18.528 16.877 20.328 ;
     RECT  16.877 19.008 16.913 20.328 ;
     RECT  16.373 14.112 17.233 14.232 ;
     RECT  16.337 29.616 17.629 29.64 ;
     RECT  16.625 15.744 17.653 16.488 ;
     RECT  17.653 15.744 17.809 16.68 ;
     RECT  16.835 21.936 17.845 28.008 ;
     RECT  17.629 29.328 18.133 29.64 ;
     RECT  16.913 19.056 18.169 20.328 ;
     RECT  18.169 18.72 18.229 20.328 ;
     RECT  17.809 15.504 18.529 16.68 ;
     RECT  16.373 3.6 18.608 13.08 ;
     RECT  17.233 14.112 18.608 14.52 ;
     RECT  18.529 15.504 18.608 16.92 ;
     RECT  18.229 18.72 18.608 20.424 ;
     RECT  17.845 21.792 18.608 28.008 ;
     RECT  18.133 29.232 18.608 29.64 ;
     RECT  18.608 2.148 18.712 30.252 ;
     RECT  18.712 2.418 18.904 29.982 ;
     RECT  18.904 18.72 19.837 29.352 ;
     RECT  18.904 14.16 19.969 17.112 ;
     RECT  19.837 22.08 20.045 29.352 ;
     RECT  19.969 14.16 20.077 17.4 ;
     RECT  18.904 3.6 20.189 13.08 ;
     RECT  20.077 14.16 20.293 17.592 ;
     RECT  20.045 24.192 20.437 29.352 ;
     RECT  20.045 22.08 21.049 23.16 ;
     RECT  20.293 13.68 21.265 17.592 ;
     RECT  19.837 18.72 21.265 20.424 ;
     RECT  20.189 3.6 21.308 12.552 ;
     RECT  21.265 13.68 21.308 20.424 ;
     RECT  21.049 22.032 21.308 23.16 ;
     RECT  20.437 24.192 21.308 29.592 ;
     RECT  21.308 2.148 21.412 30.252 ;
     RECT  21.412 2.418 21.604 29.982 ;
     RECT  21.604 19.344 21.773 20.424 ;
     RECT  21.604 18.192 21.971 18.216 ;
     RECT  21.604 3.6 22.241 12.504 ;
     RECT  21.604 13.68 22.705 16.584 ;
     RECT  21.773 19.344 22.741 19.896 ;
     RECT  21.604 21.744 22.745 29.784 ;
     RECT  22.241 4.176 23.372 12.504 ;
     RECT  22.705 13.68 23.677 16.92 ;
     RECT  23.425 18.192 23.677 18.216 ;
     RECT  23.372 3.936 23.749 12.504 ;
     RECT  23.677 13.68 23.749 18.216 ;
     RECT  22.745 21.984 23.749 29.784 ;
     RECT  22.741 19.344 23.893 19.944 ;
     RECT  23.749 21.12 23.893 29.784 ;
     RECT  23.749 3.936 24.008 18.216 ;
     RECT  23.893 19.344 24.008 29.784 ;
     RECT  24.008 2.148 24.112 30.252 ;
     RECT  24.112 2.418 24.304 29.982 ;
     RECT  24.304 19.344 24.869 29.256 ;
     RECT  24.869 19.344 25.049 29.064 ;
     RECT  24.304 18.192 25.121 18.216 ;
     RECT  25.049 19.344 25.445 22.536 ;
     RECT  25.049 23.568 25.733 29.064 ;
     RECT  25.549 18.24 25.837 18.264 ;
     RECT  25.733 26.832 26.053 29.064 ;
     RECT  24.304 4.176 26.161 16.392 ;
     RECT  25.837 18.24 26.521 18.408 ;
     RECT  25.445 19.728 26.521 22.536 ;
     RECT  26.161 4.176 26.533 17.064 ;
     RECT  26.521 18.24 26.533 22.536 ;
     RECT  26.053 26.832 26.557 29.256 ;
     RECT  26.492 32.304 26.579 32.328 ;
     RECT  26.533 4.176 26.593 22.536 ;
     RECT  26.593 4.128 26.708 22.536 ;
     RECT  25.733 23.568 26.708 25.848 ;
     RECT  26.557 26.832 26.708 29.64 ;
     RECT  26.708 2.148 26.812 30.252 ;
     RECT  26.812 2.418 27.004 29.982 ;
     RECT  27.004 3.984 27.533 18.264 ;
     RECT  27.004 19.392 27.929 29.688 ;
     RECT  27.004 2.832 28.069 2.856 ;
     RECT  27.533 3.984 28.069 17.928 ;
     RECT  27.929 19.392 28.141 29.64 ;
     RECT  28.141 19.008 28.361 29.64 ;
     RECT  28.069 2.832 28.537 17.928 ;
     RECT  28.361 19.008 28.537 19.896 ;
     RECT  28.537 2.832 28.933 19.896 ;
     RECT  28.933 2.784 29.408 19.896 ;
     RECT  28.361 20.88 29.408 29.64 ;
     RECT  29.408 2.148 29.512 30.252 ;
     RECT  29.512 2.418 29.704 29.982 ;
     RECT  29.704 17.136 29.801 29.592 ;
     RECT  29.704 2.784 29.873 16.008 ;
     RECT  29.873 4.176 29.891 16.008 ;
     RECT  29.801 17.136 30.233 22.632 ;
     RECT  30.233 17.904 30.305 22.632 ;
     RECT  29.873 2.784 30.341 3.048 ;
     RECT  29.891 4.176 30.521 15.912 ;
     RECT  30.305 19.056 30.521 22.632 ;
     RECT  29.801 23.856 30.767 29.592 ;
     RECT  30.521 19.344 30.809 22.632 ;
     RECT  30.521 15.504 31.021 15.912 ;
     RECT  30.767 23.856 31.025 29.64 ;
     RECT  31.021 15.504 31.237 16.824 ;
     RECT  30.305 17.904 31.237 17.928 ;
     RECT  30.521 4.176 31.561 14.232 ;
     RECT  31.237 15.504 31.561 17.928 ;
     RECT  30.341 3.024 31.597 3.048 ;
     RECT  31.561 4.176 31.597 17.928 ;
     RECT  30.809 19.344 31.669 22.584 ;
     RECT  31.597 3.024 31.921 17.928 ;
     RECT  31.669 19.296 31.921 22.584 ;
     RECT  31.921 2.832 32.108 22.584 ;
     RECT  31.025 23.904 32.108 29.64 ;
     RECT  32.108 2.148 32.212 30.252 ;
     RECT  32.212 2.418 32.404 29.982 ;
     RECT  32.404 17.088 32.933 19.896 ;
     RECT  32.933 17.088 33.113 17.736 ;
     RECT  32.404 2.832 33.149 4.968 ;
     RECT  33.149 2.832 33.221 2.904 ;
     RECT  32.404 6.048 33.473 7.752 ;
     RECT  32.404 20.928 33.509 23.736 ;
     RECT  33.473 7.68 33.757 7.752 ;
     RECT  32.404 8.736 33.757 9.096 ;
     RECT  33.509 21.168 33.937 23.736 ;
     RECT  32.404 24.72 33.937 29.784 ;
     RECT  33.757 7.68 34.117 9.096 ;
     RECT  32.404 10.32 34.117 15.816 ;
     RECT  33.113 17.136 34.117 17.736 ;
     RECT  33.149 4.176 34.369 4.968 ;
     RECT  33.221 2.832 34.808 2.856 ;
     RECT  34.369 3.936 34.808 4.968 ;
     RECT  33.473 6.048 34.808 6.696 ;
     RECT  34.117 7.68 34.808 17.736 ;
     RECT  32.933 18.768 34.808 19.896 ;
     RECT  33.937 21.168 34.808 29.784 ;
     RECT  34.808 2.148 34.912 30.252 ;
     RECT  34.912 2.418 35.104 29.982 ;
     RECT  35.104 24.624 35.219 29.784 ;
     RECT  35.219 28.464 35.273 29.784 ;
     RECT  35.104 3.936 35.309 5.016 ;
     RECT  35.309 3.936 35.381 4.824 ;
     RECT  35.104 6.048 35.381 19.896 ;
     RECT  35.273 29.04 35.417 29.784 ;
     RECT  35.381 6.048 35.548 19.8 ;
     RECT  35.381 4.128 35.669 4.824 ;
     RECT  35.548 6.048 35.669 19.32 ;
     RECT  35.669 4.8 35.692 4.824 ;
     RECT  35.417 29.328 35.741 29.784 ;
     RECT  35.669 6.048 35.777 19.272 ;
     RECT  35.219 24.624 35.885 27.336 ;
     RECT  35.777 6.048 35.921 16.44 ;
     RECT  35.777 17.424 35.921 19.272 ;
     RECT  35.885 25.92 36.137 27.336 ;
     RECT  35.921 6.048 36.281 15.96 ;
     RECT  35.104 21.696 36.709 22.968 ;
     RECT  35.885 24.624 37.033 24.936 ;
     RECT  36.137 25.92 37.033 26.856 ;
     RECT  36.709 20.88 37.093 22.968 ;
     RECT  35.921 17.424 37.249 18.792 ;
     RECT  37.093 20.88 37.249 23.352 ;
     RECT  36.281 6.048 37.357 6.696 ;
     RECT  36.281 7.68 37.357 15.96 ;
     RECT  37.357 6.048 37.429 15.96 ;
     RECT  35.741 29.568 37.465 29.784 ;
     RECT  37.429 5.472 37.501 15.96 ;
     RECT  37.249 17.424 37.501 18.984 ;
     RECT  36.529 2.304 37.508 2.328 ;
     RECT  36.817 4.224 37.508 4.248 ;
     RECT  37.501 5.472 37.508 18.984 ;
     RECT  37.249 20.592 37.508 23.352 ;
     RECT  37.033 24.624 37.508 26.856 ;
     RECT  37.465 29.04 37.508 29.784 ;
     RECT  37.508 2.148 37.612 30.252 ;
     RECT  37.612 2.418 37.804 29.982 ;
     RECT  37.804 23.328 37.829 23.352 ;
     RECT  37.804 15.504 37.955 16.392 ;
     RECT  37.804 17.472 37.955 19.944 ;
     RECT  37.804 14.16 37.973 14.184 ;
     RECT  37.804 10.272 38.081 13.032 ;
     RECT  37.955 15.792 38.081 16.392 ;
     RECT  38.081 10.272 38.195 11.976 ;
     RECT  37.955 17.472 38.261 17.688 ;
     RECT  38.195 10.272 38.333 10.968 ;
     RECT  37.955 18.96 38.333 19.944 ;
     RECT  37.804 29.04 38.657 29.064 ;
     RECT  37.804 25.632 38.693 27.096 ;
     RECT  38.333 10.272 38.729 10.68 ;
     RECT  38.693 25.632 38.771 26.808 ;
     RECT  38.261 17.616 38.801 17.688 ;
     RECT  37.804 6.816 38.837 9.048 ;
     RECT  38.333 19.344 38.837 19.944 ;
     RECT  38.771 26.112 38.837 26.136 ;
     RECT  38.837 7.344 38.869 9.048 ;
     RECT  38.837 19.92 38.873 19.944 ;
     RECT  37.804 21.936 38.873 22.056 ;
     RECT  38.081 13.008 38.909 13.032 ;
     RECT  38.869 7.344 38.915 9.144 ;
     RECT  38.729 10.656 38.981 10.68 ;
     RECT  38.081 15.792 39.053 15.816 ;
     RECT  37.804 4.224 39.107 4.248 ;
     RECT  38.801 17.616 39.197 17.64 ;
     RECT  39.061 5.424 40.208 5.448 ;
     RECT  38.915 7.344 40.208 7.368 ;
     RECT  38.915 9.12 40.208 9.144 ;
     RECT  38.195 11.952 40.208 11.976 ;
     RECT  39.841 13.584 40.208 13.608 ;
     RECT  38.873 22.032 40.208 22.056 ;
     RECT  39.877 26.784 40.208 26.808 ;
     RECT  40.208 2.148 40.312 30.252 ;
     RECT  40.312 2.418 40.504 29.982 ;
     RECT  40.504 13.296 41.497 13.992 ;
     RECT  40.504 15.216 41.497 16.296 ;
     RECT  40.504 6.96 41.533 8.712 ;
     RECT  40.504 26.256 41.533 28.584 ;
     RECT  40.504 20.112 41.569 21 ;
     RECT  40.504 22.416 41.569 22.824 ;
     RECT  41.497 13.296 41.605 16.776 ;
     RECT  41.533 6.96 42.109 9.576 ;
     RECT  41.533 26.256 42.109 29.064 ;
     RECT  41.605 13.104 42.145 16.776 ;
     RECT  41.569 20.016 42.145 22.824 ;
     RECT  42.109 26.16 42.145 29.064 ;
     RECT  42.109 6.96 43.081 9.864 ;
     RECT  42.145 19.92 43.081 22.824 ;
     RECT  43.081 6.864 43.164 9.864 ;
     RECT  42.145 13.008 43.164 16.776 ;
     RECT  43.081 19.92 43.164 22.92 ;
     RECT  42.145 26.064 43.164 29.064 ;
    LAYER M5 ;
     RECT  2.4 2.137 2.52 2.151 ;
     RECT  5.1 2.137 5.22 2.151 ;
     RECT  7.8 2.137 7.92 2.151 ;
     RECT  10.5 2.137 10.62 2.151 ;
     RECT  13.2 2.137 13.32 2.151 ;
     RECT  15.9 2.137 16.02 2.151 ;
     RECT  18.6 2.137 18.72 2.151 ;
     RECT  21.3 2.137 21.42 2.151 ;
     RECT  24 2.137 24.12 2.151 ;
     RECT  26.7 2.137 26.82 2.151 ;
     RECT  29.4 2.137 29.52 2.151 ;
     RECT  32.1 2.137 32.22 2.151 ;
     RECT  34.8 2.137 34.92 2.151 ;
     RECT  37.5 2.137 37.62 2.151 ;
     RECT  40.2 2.137 40.32 2.151 ;
     RECT  24 2.151 24.312 3.925 ;
     RECT  26.7 2.151 27.012 4.501 ;
     RECT  23.424 3.925 24.312 4.643 ;
     RECT  34.8 2.151 35.112 4.789 ;
     RECT  21.3 2.151 21.612 5.077 ;
     RECT  39.072 4.213 39.096 5.459 ;
     RECT  13.2 2.151 13.512 5.653 ;
     RECT  24 4.643 24.312 5.749 ;
     RECT  29.4 2.151 29.712 5.749 ;
     RECT  29.28 5.749 29.712 5.987 ;
     RECT  22.8 5.797 22.824 6.227 ;
     RECT  24 5.749 25.128 6.323 ;
     RECT  15.9 2.151 16.212 6.757 ;
     RECT  13.104 5.653 13.512 6.805 ;
     RECT  34.8 4.789 35.64 6.805 ;
     RECT  13.104 6.805 13.656 6.851 ;
     RECT  20.544 5.077 21.612 6.851 ;
     RECT  10.5 2.151 10.812 6.853 ;
     RECT  24 6.323 24.312 6.901 ;
     RECT  25.296 6.373 25.32 6.947 ;
     RECT  23.904 6.901 24.312 7.091 ;
     RECT  15.9 6.757 17.064 7.189 ;
     RECT  37.5 2.151 37.812 7.189 ;
     RECT  21.072 6.851 21.612 7.381 ;
     RECT  13.2 6.851 13.656 7.763 ;
     RECT  34.8 6.805 36.024 7.765 ;
     RECT  18.6 2.151 18.912 7.909 ;
     RECT  14.976 7.189 17.064 8.003 ;
     RECT  21.072 7.381 22.104 8.064 ;
     RECT  7.8 2.151 8.112 8.149 ;
     RECT  9.936 6.853 10.812 8.195 ;
     RECT  18.6 7.909 19.032 8.245 ;
     RECT  18.192 8.245 19.032 8.291 ;
     RECT  37.5 7.189 37.944 8.293 ;
     RECT  26.4 4.501 27.012 8.341 ;
     RECT  7.8 8.149 8.52 8.485 ;
     RECT  18.192 8.291 18.912 8.531 ;
     RECT  21.3 8.064 22.104 8.579 ;
     RECT  2.4 2.151 2.712 8.581 ;
     RECT  13.2 7.763 13.512 8.869 ;
     RECT  34.8 7.765 36.312 9.013 ;
     RECT  37.5 8.293 38.904 9.013 ;
     RECT  2.304 8.581 2.712 9.059 ;
     RECT  13.2 8.869 14.376 9.059 ;
     RECT  26.4 8.341 27.624 9.155 ;
     RECT  34.8 9.013 38.904 9.155 ;
     RECT  15.9 8.003 16.632 9.253 ;
     RECT  14.832 9.253 16.632 9.349 ;
     RECT  14.832 9.349 16.968 9.395 ;
     RECT  14.832 9.395 14.856 9.539 ;
     RECT  15.9 9.395 16.968 9.539 ;
     RECT  34.8 9.155 38.712 9.731 ;
     RECT  5.1 2.151 5.412 10.213 ;
     RECT  37.5 9.731 38.712 10.307 ;
     RECT  34.8 9.731 36.312 10.453 ;
     RECT  13.2 9.059 13.512 10.645 ;
     RECT  29.4 5.987 29.712 10.693 ;
     RECT  21.3 8.579 21.612 10.741 ;
     RECT  5.1 10.213 6.072 10.883 ;
     RECT  10.272 8.195 10.812 11.125 ;
     RECT  37.5 10.307 38.184 11.125 ;
     RECT  26.4 9.155 27.012 11.365 ;
     RECT  5.1 10.883 5.412 11.893 ;
     RECT  37.392 11.125 38.184 11.987 ;
     RECT  29.4 10.693 30.024 12.035 ;
     RECT  37.392 11.987 37.944 12.035 ;
     RECT  34.272 10.453 36.312 12.083 ;
     RECT  29.4 12.035 29.712 12.325 ;
     RECT  7.8 8.485 8.808 12.421 ;
     RECT  9.84 11.125 10.812 12.421 ;
     RECT  26.112 11.365 27.012 12.467 ;
     RECT  20.784 10.741 21.612 12.563 ;
     RECT  34.704 12.083 36.312 12.563 ;
     RECT  5.1 11.893 5.736 12.755 ;
     RECT  34.8 12.563 36.312 12.803 ;
     RECT  13.2 10.645 13.608 13.045 ;
     RECT  7.8 12.421 10.812 13.139 ;
     RECT  36.288 12.803 36.312 13.283 ;
     RECT  26.7 12.467 27.012 13.429 ;
     RECT  13.2 13.045 13.944 13.525 ;
     RECT  21.3 12.563 21.612 13.669 ;
     RECT  9.696 13.139 10.812 13.811 ;
     RECT  20.544 13.669 22.536 13.861 ;
     RECT  24 7.091 24.312 13.861 ;
     RECT  20.544 13.861 24.312 14.051 ;
     RECT  24 14.051 24.312 14.101 ;
     RECT  34.8 12.803 35.304 14.101 ;
     RECT  7.8 13.139 8.112 14.197 ;
     RECT  33.936 14.101 35.304 14.197 ;
     RECT  5.1 12.755 5.688 14.387 ;
     RECT  13.2 13.525 14.808 14.387 ;
     RECT  7.8 14.197 8.568 14.867 ;
     RECT  20.544 14.051 22.536 14.867 ;
     RECT  33.936 14.197 36.168 14.867 ;
     RECT  21.3 14.867 22.536 14.915 ;
     RECT  28.944 12.325 29.712 14.917 ;
     RECT  33.936 14.867 35.304 15.491 ;
     RECT  37.5 12.035 37.944 15.539 ;
     RECT  18.6 8.531 18.912 15.637 ;
     RECT  24 14.101 24.408 15.683 ;
     RECT  26.208 13.429 27.012 15.683 ;
     RECT  15.9 9.539 16.872 15.829 ;
     RECT  18.6 15.637 19.464 15.829 ;
     RECT  13.2 14.387 14.76 16.019 ;
     RECT  28.944 14.917 29.88 16.019 ;
     RECT  15.9 15.829 19.464 16.211 ;
     RECT  34.8 15.491 35.304 16.405 ;
     RECT  5.1 14.387 5.412 16.501 ;
     RECT  6.768 13.477 6.792 16.501 ;
     RECT  17.664 16.211 19.464 16.691 ;
     RECT  10.368 13.811 10.812 16.933 ;
     RECT  9.84 16.933 10.812 17.509 ;
     RECT  0.144 17.413 0.168 17.603 ;
     RECT  34.8 16.405 35.784 17.701 ;
     RECT  34.416 17.701 35.784 17.747 ;
     RECT  26.7 15.683 27.012 17.893 ;
     RECT  9.744 17.509 10.812 17.989 ;
     RECT  11.952 16.837 11.976 17.989 ;
     RECT  37.5 15.539 37.812 17.989 ;
     RECT  9.744 17.989 11.976 18.035 ;
     RECT  13.2 16.019 14.232 18.035 ;
     RECT  21.3 14.915 21.612 18.181 ;
     RECT  5.1 16.501 6.792 18.227 ;
     RECT  34.416 17.747 35.112 18.757 ;
     RECT  6.528 18.227 6.792 18.803 ;
     RECT  0.144 18.805 0.168 18.995 ;
     RECT  9.744 18.035 11.496 18.995 ;
     RECT  37.5 17.989 37.944 18.995 ;
     RECT  18.6 16.691 18.912 19.333 ;
     RECT  24 15.683 24.312 19.333 ;
     RECT  34.416 18.757 35.496 19.811 ;
     RECT  21.3 18.181 21.96 19.859 ;
     RECT  15.9 16.211 16.212 19.909 ;
     RECT  15.9 19.909 16.824 20.293 ;
     RECT  18.24 19.333 18.912 20.293 ;
     RECT  13.2 18.035 14.136 20.339 ;
     RECT  15.9 20.293 18.912 20.389 ;
     RECT  9.744 18.995 11.4 20.819 ;
     RECT  28.944 16.019 29.712 20.821 ;
     RECT  26.544 17.893 27.012 20.917 ;
     RECT  28.944 20.821 29.832 20.963 ;
     RECT  26.544 20.917 27.144 21.013 ;
     RECT  6.528 18.803 6.552 21.109 ;
     RECT  6.528 21.109 6.792 21.155 ;
     RECT  9.744 20.819 10.812 21.155 ;
     RECT  15.9 20.389 19.8 21.155 ;
     RECT  23.904 19.333 25.032 21.155 ;
     RECT  31.056 20.485 31.08 21.155 ;
     RECT  13.2 20.339 13.704 21.539 ;
     RECT  26.544 21.013 27.72 21.875 ;
     RECT  37.5 18.995 37.812 22.165 ;
     RECT  26.544 21.875 27.144 22.499 ;
     RECT  9.312 22.261 9.336 22.501 ;
     RECT  10.5 21.155 10.812 22.501 ;
     RECT  32.1 2.151 32.412 22.549 ;
     RECT  9.312 22.501 10.812 22.595 ;
     RECT  9.6 22.595 10.812 22.643 ;
     RECT  34.416 19.811 35.112 22.645 ;
     RECT  13.2 21.539 13.512 22.741 ;
     RECT  22.8 22.501 22.824 22.787 ;
     RECT  24 21.155 25.032 22.835 ;
     RECT  6.768 21.155 6.792 23.269 ;
     RECT  7.8 14.867 8.112 23.269 ;
     RECT  0.144 23.125 0.168 23.315 ;
     RECT  32.1 22.549 33.048 23.363 ;
     RECT  13.056 22.741 13.512 23.699 ;
     RECT  15.9 21.155 18.912 23.699 ;
     RECT  5.1 18.227 5.412 23.845 ;
     RECT  4.56 23.845 5.412 24.181 ;
     RECT  34.128 22.645 35.112 24.325 ;
     RECT  4.128 24.181 5.412 24.467 ;
     RECT  21.3 19.859 21.612 24.469 ;
     RECT  19.968 22.549 19.992 24.563 ;
     RECT  24 22.835 24.312 24.613 ;
     RECT  4.56 24.467 5.412 24.803 ;
     RECT  26.544 22.499 27.012 24.901 ;
     RECT  0.144 24.709 0.168 24.995 ;
     RECT  6.768 23.269 8.112 25.139 ;
     RECT  33.984 24.325 35.112 25.331 ;
     RECT  37.104 22.165 37.812 25.621 ;
     RECT  10.5 22.643 10.812 25.717 ;
     RECT  34.128 25.331 35.112 25.955 ;
     RECT  34.8 25.955 35.112 25.957 ;
     RECT  24 24.613 24.552 26.003 ;
     RECT  21.3 24.469 21.72 26.291 ;
     RECT  28.944 20.963 29.712 26.291 ;
     RECT  13.2 23.699 13.512 26.293 ;
     RECT  37.104 25.621 38.76 26.339 ;
     RECT  25.776 24.901 27.012 26.341 ;
     RECT  15.9 23.699 16.212 26.437 ;
     RECT  17.664 23.699 18.912 26.437 ;
     RECT  30.816 26.485 30.84 26.629 ;
     RECT  10.224 25.717 10.812 26.771 ;
     RECT  37.5 26.339 38.76 26.819 ;
     RECT  24 26.003 24.312 26.821 ;
     RECT  23.904 26.821 24.312 26.963 ;
     RECT  7.056 25.139 8.112 27.059 ;
     RECT  22.8 26.869 22.824 27.203 ;
     RECT  15.9 26.437 18.912 27.685 ;
     RECT  15.264 27.685 18.912 27.733 ;
     RECT  29.4 26.291 29.712 27.877 ;
     RECT  30.768 26.629 30.84 27.877 ;
     RECT  15.264 27.733 19.608 27.971 ;
     RECT  25.776 26.341 27.144 27.971 ;
     RECT  15.264 27.971 17.16 28.019 ;
     RECT  25.824 27.971 27.144 28.309 ;
     RECT  25.824 28.309 27.816 28.499 ;
     RECT  12.768 26.293 13.512 28.691 ;
     RECT  26.544 28.499 27.816 28.741 ;
     RECT  29.4 27.877 30.84 28.741 ;
     RECT  26.544 28.741 30.84 28.931 ;
     RECT  15.264 28.019 16.212 28.979 ;
     RECT  18.6 27.971 19.608 28.979 ;
     RECT  28.848 28.931 30.84 28.979 ;
     RECT  28.848 28.979 29.712 29.123 ;
     RECT  30.816 28.979 30.84 29.651 ;
     RECT  26.544 28.931 27.816 29.699 ;
     RECT  22.704 28.981 22.728 29.795 ;
     RECT  34.8 25.957 35.88 29.795 ;
     RECT  2.4 9.059 2.712 30.249 ;
     RECT  5.1 24.803 5.412 30.249 ;
     RECT  7.8 27.059 8.112 30.249 ;
     RECT  10.5 26.771 10.812 30.249 ;
     RECT  13.2 28.691 13.512 30.249 ;
     RECT  15.9 28.979 16.212 30.249 ;
     RECT  18.6 28.979 18.912 30.249 ;
     RECT  21.3 26.291 21.612 30.249 ;
     RECT  24 26.963 24.312 30.249 ;
     RECT  26.544 29.699 27.012 30.249 ;
     RECT  29.4 29.123 29.712 30.249 ;
     RECT  32.1 23.363 32.412 30.249 ;
     RECT  34.8 29.795 35.112 30.249 ;
     RECT  37.5 26.819 37.812 30.249 ;
     RECT  40.2 2.151 40.512 30.249 ;
     RECT  2.4 30.249 2.52 30.263 ;
     RECT  5.1 30.249 5.22 30.263 ;
     RECT  7.8 30.249 7.92 30.263 ;
     RECT  10.5 30.249 10.62 30.263 ;
     RECT  13.2 30.249 13.32 30.263 ;
     RECT  15.9 30.249 16.02 30.263 ;
     RECT  18.6 30.249 18.72 30.263 ;
     RECT  21.3 30.249 21.42 30.263 ;
     RECT  24 30.249 24.12 30.263 ;
     RECT  26.544 30.249 26.82 30.263 ;
     RECT  29.4 30.249 29.52 30.263 ;
     RECT  32.1 30.249 32.22 30.263 ;
     RECT  34.8 30.249 34.92 30.263 ;
     RECT  37.5 30.249 37.62 30.263 ;
     RECT  40.2 30.249 40.32 30.263 ;
     RECT  26.544 30.263 26.568 32.339 ;
  END
END hbfd_land_136_WE
END LIBRARY
